##
## LEF for PtnCells ;
## created by Innovus v15.23-s045_1 on Fri Mar 20 17:59:08 2026
##

VERSION 5.8 ;

BUSBITCHARS "[]" ;
DIVIDERCHAR "/" ;

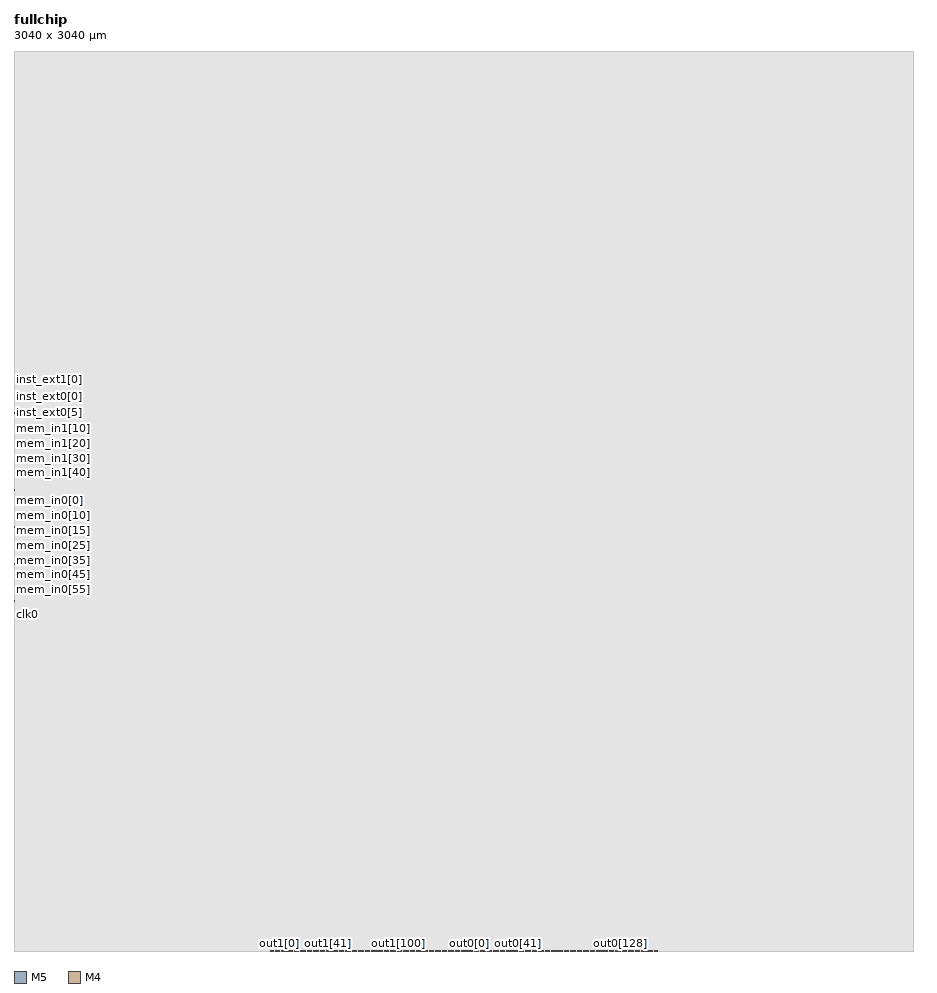
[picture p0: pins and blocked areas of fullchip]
MACRO fullchip
  CLASS BLOCK ;
  SIZE 3040.0000 BY 3040.0000 ;
  FOREIGN fullchip 0.0000 0.0000 ;
  ORIGIN 0 0 ;
  SYMMETRY X Y R90 ;
  PIN reset0
    DIRECTION INPUT ;
    USE SIGNAL ;
    PORT
      LAYER M5 ;
        RECT 0.0000 1147.1500 0.5200 1147.2500 ;
    END
  END reset0
  PIN reset1
    DIRECTION INPUT ;
    USE SIGNAL ;
    PORT
      LAYER M5 ;
        RECT 0.0000 1152.1500 0.5200 1152.2500 ;
    END
  END reset1
  PIN clk0
    DIRECTION INPUT ;
    USE SIGNAL ;
    PORT
      LAYER M5 ;
        RECT 0.0000 1137.1500 0.5200 1137.2500 ;
    END
  END clk0
  PIN clk1
    DIRECTION INPUT ;
    USE SIGNAL ;
    PORT
      LAYER M5 ;
        RECT 0.0000 1142.1500 0.5200 1142.2500 ;
    END
  END clk1
  PIN start0
    DIRECTION INPUT ;
    USE SIGNAL ;
    PORT
      LAYER M5 ;
        RECT 0.0000 1157.1500 0.5200 1157.2500 ;
    END
  END start0
  PIN start1
    DIRECTION INPUT ;
    USE SIGNAL ;
    PORT
      LAYER M5 ;
        RECT 0.0000 1162.1500 0.5200 1162.2500 ;
    END
  END start1
  PIN set_mode0
    DIRECTION INPUT ;
    USE SIGNAL ;
    PORT
      LAYER M5 ;
        RECT 0.0000 1167.1500 0.5200 1167.2500 ;
    END
  END set_mode0
  PIN set_mode1
    DIRECTION INPUT ;
    USE SIGNAL ;
    PORT
      LAYER M5 ;
        RECT 0.0000 1172.1500 0.5200 1172.2500 ;
    END
  END set_mode1
  PIN mode_in0[2]
    DIRECTION INPUT ;
    USE SIGNAL ;
    PORT
      LAYER M5 ;
        RECT 0.0000 1177.1500 0.5200 1177.2500 ;
    END
  END mode_in0[2]
  PIN mode_in0[1]
    DIRECTION INPUT ;
    USE SIGNAL ;
    PORT
      LAYER M5 ;
        RECT 0.0000 1182.1500 0.5200 1182.2500 ;
    END
  END mode_in0[1]
  PIN mode_in0[0]
    DIRECTION INPUT ;
    USE SIGNAL ;
    PORT
      LAYER M5 ;
        RECT 0.0000 1187.1500 0.5200 1187.2500 ;
    END
  END mode_in0[0]
  PIN mode_in1[2]
    DIRECTION INPUT ;
    USE SIGNAL ;
    PORT
      LAYER M5 ;
        RECT 0.0000 1192.1500 0.5200 1192.2500 ;
    END
  END mode_in1[2]
  PIN mode_in1[1]
    DIRECTION INPUT ;
    USE SIGNAL ;
    PORT
      LAYER M5 ;
        RECT 0.0000 1197.1500 0.5200 1197.2500 ;
    END
  END mode_in1[1]
  PIN mode_in1[0]
    DIRECTION INPUT ;
    USE SIGNAL ;
    PORT
      LAYER M5 ;
        RECT 0.0000 1202.1500 0.5200 1202.2500 ;
    END
  END mode_in1[0]
  PIN mem_in0[63]
    DIRECTION INPUT ;
    USE SIGNAL ;
    PORT
      LAYER M5 ;
        RECT 0.0000 1207.1500 0.5200 1207.2500 ;
    END
  END mem_in0[63]
  PIN mem_in0[62]
    DIRECTION INPUT ;
    USE SIGNAL ;
    PORT
      LAYER M5 ;
        RECT 0.0000 1212.1500 0.5200 1212.2500 ;
    END
  END mem_in0[62]
  PIN mem_in0[61]
    DIRECTION INPUT ;
    USE SIGNAL ;
    PORT
      LAYER M5 ;
        RECT 0.0000 1217.1500 0.5200 1217.2500 ;
    END
  END mem_in0[61]
  PIN mem_in0[60]
    DIRECTION INPUT ;
    USE SIGNAL ;
    PORT
      LAYER M5 ;
        RECT 0.0000 1222.1500 0.5200 1222.2500 ;
    END
  END mem_in0[60]
  PIN mem_in0[59]
    DIRECTION INPUT ;
    USE SIGNAL ;
    PORT
      LAYER M5 ;
        RECT 0.0000 1227.1500 0.5200 1227.2500 ;
    END
  END mem_in0[59]
  PIN mem_in0[58]
    DIRECTION INPUT ;
    USE SIGNAL ;
    PORT
      LAYER M5 ;
        RECT 0.0000 1232.1500 0.5200 1232.2500 ;
    END
  END mem_in0[58]
  PIN mem_in0[57]
    DIRECTION INPUT ;
    USE SIGNAL ;
    PORT
      LAYER M5 ;
        RECT 0.0000 1237.1500 0.5200 1237.2500 ;
    END
  END mem_in0[57]
  PIN mem_in0[56]
    DIRECTION INPUT ;
    USE SIGNAL ;
    PORT
      LAYER M5 ;
        RECT 0.0000 1242.1500 0.5200 1242.2500 ;
    END
  END mem_in0[56]
  PIN mem_in0[55]
    DIRECTION INPUT ;
    USE SIGNAL ;
    PORT
      LAYER M5 ;
        RECT 0.0000 1247.1500 0.5200 1247.2500 ;
    END
  END mem_in0[55]
  PIN mem_in0[54]
    DIRECTION INPUT ;
    USE SIGNAL ;
    PORT
      LAYER M5 ;
        RECT 0.0000 1252.1500 0.5200 1252.2500 ;
    END
  END mem_in0[54]
  PIN mem_in0[53]
    DIRECTION INPUT ;
    USE SIGNAL ;
    PORT
      LAYER M5 ;
        RECT 0.0000 1257.1500 0.5200 1257.2500 ;
    END
  END mem_in0[53]
  PIN mem_in0[52]
    DIRECTION INPUT ;
    USE SIGNAL ;
    PORT
      LAYER M5 ;
        RECT 0.0000 1262.1500 0.5200 1262.2500 ;
    END
  END mem_in0[52]
  PIN mem_in0[51]
    DIRECTION INPUT ;
    USE SIGNAL ;
    PORT
      LAYER M5 ;
        RECT 0.0000 1267.1500 0.5200 1267.2500 ;
    END
  END mem_in0[51]
  PIN mem_in0[50]
    DIRECTION INPUT ;
    USE SIGNAL ;
    PORT
      LAYER M5 ;
        RECT 0.0000 1272.1500 0.5200 1272.2500 ;
    END
  END mem_in0[50]
  PIN mem_in0[49]
    DIRECTION INPUT ;
    USE SIGNAL ;
    PORT
      LAYER M5 ;
        RECT 0.0000 1277.1500 0.5200 1277.2500 ;
    END
  END mem_in0[49]
  PIN mem_in0[48]
    DIRECTION INPUT ;
    USE SIGNAL ;
    PORT
      LAYER M5 ;
        RECT 0.0000 1282.1500 0.5200 1282.2500 ;
    END
  END mem_in0[48]
  PIN mem_in0[47]
    DIRECTION INPUT ;
    USE SIGNAL ;
    PORT
      LAYER M5 ;
        RECT 0.0000 1287.1500 0.5200 1287.2500 ;
    END
  END mem_in0[47]
  PIN mem_in0[46]
    DIRECTION INPUT ;
    USE SIGNAL ;
    PORT
      LAYER M5 ;
        RECT 0.0000 1292.1500 0.5200 1292.2500 ;
    END
  END mem_in0[46]
  PIN mem_in0[45]
    DIRECTION INPUT ;
    USE SIGNAL ;
    PORT
      LAYER M5 ;
        RECT 0.0000 1297.1500 0.5200 1297.2500 ;
    END
  END mem_in0[45]
  PIN mem_in0[44]
    DIRECTION INPUT ;
    USE SIGNAL ;
    PORT
      LAYER M5 ;
        RECT 0.0000 1302.1500 0.5200 1302.2500 ;
    END
  END mem_in0[44]
  PIN mem_in0[43]
    DIRECTION INPUT ;
    USE SIGNAL ;
    PORT
      LAYER M5 ;
        RECT 0.0000 1307.1500 0.5200 1307.2500 ;
    END
  END mem_in0[43]
  PIN mem_in0[42]
    DIRECTION INPUT ;
    USE SIGNAL ;
    PORT
      LAYER M5 ;
        RECT 0.0000 1312.1500 0.5200 1312.2500 ;
    END
  END mem_in0[42]
  PIN mem_in0[41]
    DIRECTION INPUT ;
    USE SIGNAL ;
    PORT
      LAYER M5 ;
        RECT 0.0000 1317.1500 0.5200 1317.2500 ;
    END
  END mem_in0[41]
  PIN mem_in0[40]
    DIRECTION INPUT ;
    USE SIGNAL ;
    PORT
      LAYER M5 ;
        RECT 0.0000 1322.1500 0.5200 1322.2500 ;
    END
  END mem_in0[40]
  PIN mem_in0[39]
    DIRECTION INPUT ;
    USE SIGNAL ;
    PORT
      LAYER M5 ;
        RECT 0.0000 1327.1500 0.5200 1327.2500 ;
    END
  END mem_in0[39]
  PIN mem_in0[38]
    DIRECTION INPUT ;
    USE SIGNAL ;
    PORT
      LAYER M5 ;
        RECT 0.0000 1332.1500 0.5200 1332.2500 ;
    END
  END mem_in0[38]
  PIN mem_in0[37]
    DIRECTION INPUT ;
    USE SIGNAL ;
    PORT
      LAYER M5 ;
        RECT 0.0000 1337.1500 0.5200 1337.2500 ;
    END
  END mem_in0[37]
  PIN mem_in0[36]
    DIRECTION INPUT ;
    USE SIGNAL ;
    PORT
      LAYER M5 ;
        RECT 0.0000 1342.1500 0.5200 1342.2500 ;
    END
  END mem_in0[36]
  PIN mem_in0[35]
    DIRECTION INPUT ;
    USE SIGNAL ;
    PORT
      LAYER M5 ;
        RECT 0.0000 1347.1500 0.5200 1347.2500 ;
    END
  END mem_in0[35]
  PIN mem_in0[34]
    DIRECTION INPUT ;
    USE SIGNAL ;
    PORT
      LAYER M5 ;
        RECT 0.0000 1352.1500 0.5200 1352.2500 ;
    END
  END mem_in0[34]
  PIN mem_in0[33]
    DIRECTION INPUT ;
    USE SIGNAL ;
    PORT
      LAYER M5 ;
        RECT 0.0000 1357.1500 0.5200 1357.2500 ;
    END
  END mem_in0[33]
  PIN mem_in0[32]
    DIRECTION INPUT ;
    USE SIGNAL ;
    PORT
      LAYER M5 ;
        RECT 0.0000 1362.1500 0.5200 1362.2500 ;
    END
  END mem_in0[32]
  PIN mem_in0[31]
    DIRECTION INPUT ;
    USE SIGNAL ;
    PORT
      LAYER M5 ;
        RECT 0.0000 1367.1500 0.5200 1367.2500 ;
    END
  END mem_in0[31]
  PIN mem_in0[30]
    DIRECTION INPUT ;
    USE SIGNAL ;
    PORT
      LAYER M5 ;
        RECT 0.0000 1372.1500 0.5200 1372.2500 ;
    END
  END mem_in0[30]
  PIN mem_in0[29]
    DIRECTION INPUT ;
    USE SIGNAL ;
    PORT
      LAYER M5 ;
        RECT 0.0000 1377.1500 0.5200 1377.2500 ;
    END
  END mem_in0[29]
  PIN mem_in0[28]
    DIRECTION INPUT ;
    USE SIGNAL ;
    PORT
      LAYER M5 ;
        RECT 0.0000 1382.1500 0.5200 1382.2500 ;
    END
  END mem_in0[28]
  PIN mem_in0[27]
    DIRECTION INPUT ;
    USE SIGNAL ;
    PORT
      LAYER M5 ;
        RECT 0.0000 1387.1500 0.5200 1387.2500 ;
    END
  END mem_in0[27]
  PIN mem_in0[26]
    DIRECTION INPUT ;
    USE SIGNAL ;
    PORT
      LAYER M5 ;
        RECT 0.0000 1392.1500 0.5200 1392.2500 ;
    END
  END mem_in0[26]
  PIN mem_in0[25]
    DIRECTION INPUT ;
    USE SIGNAL ;
    PORT
      LAYER M5 ;
        RECT 0.0000 1397.1500 0.5200 1397.2500 ;
    END
  END mem_in0[25]
  PIN mem_in0[24]
    DIRECTION INPUT ;
    USE SIGNAL ;
    PORT
      LAYER M5 ;
        RECT 0.0000 1402.1500 0.5200 1402.2500 ;
    END
  END mem_in0[24]
  PIN mem_in0[23]
    DIRECTION INPUT ;
    USE SIGNAL ;
    PORT
      LAYER M5 ;
        RECT 0.0000 1407.1500 0.5200 1407.2500 ;
    END
  END mem_in0[23]
  PIN mem_in0[22]
    DIRECTION INPUT ;
    USE SIGNAL ;
    PORT
      LAYER M5 ;
        RECT 0.0000 1412.1500 0.5200 1412.2500 ;
    END
  END mem_in0[22]
  PIN mem_in0[21]
    DIRECTION INPUT ;
    USE SIGNAL ;
    PORT
      LAYER M5 ;
        RECT 0.0000 1417.1500 0.5200 1417.2500 ;
    END
  END mem_in0[21]
  PIN mem_in0[20]
    DIRECTION INPUT ;
    USE SIGNAL ;
    PORT
      LAYER M5 ;
        RECT 0.0000 1422.1500 0.5200 1422.2500 ;
    END
  END mem_in0[20]
  PIN mem_in0[19]
    DIRECTION INPUT ;
    USE SIGNAL ;
    PORT
      LAYER M5 ;
        RECT 0.0000 1427.1500 0.5200 1427.2500 ;
    END
  END mem_in0[19]
  PIN mem_in0[18]
    DIRECTION INPUT ;
    USE SIGNAL ;
    PORT
      LAYER M5 ;
        RECT 0.0000 1432.1500 0.5200 1432.2500 ;
    END
  END mem_in0[18]
  PIN mem_in0[17]
    DIRECTION INPUT ;
    USE SIGNAL ;
    PORT
      LAYER M5 ;
        RECT 0.0000 1437.1500 0.5200 1437.2500 ;
    END
  END mem_in0[17]
  PIN mem_in0[16]
    DIRECTION INPUT ;
    USE SIGNAL ;
    PORT
      LAYER M5 ;
        RECT 0.0000 1442.1500 0.5200 1442.2500 ;
    END
  END mem_in0[16]
  PIN mem_in0[15]
    DIRECTION INPUT ;
    USE SIGNAL ;
    PORT
      LAYER M5 ;
        RECT 0.0000 1447.1500 0.5200 1447.2500 ;
    END
  END mem_in0[15]
  PIN mem_in0[14]
    DIRECTION INPUT ;
    USE SIGNAL ;
    PORT
      LAYER M5 ;
        RECT 0.0000 1452.1500 0.5200 1452.2500 ;
    END
  END mem_in0[14]
  PIN mem_in0[13]
    DIRECTION INPUT ;
    USE SIGNAL ;
    PORT
      LAYER M5 ;
        RECT 0.0000 1457.1500 0.5200 1457.2500 ;
    END
  END mem_in0[13]
  PIN mem_in0[12]
    DIRECTION INPUT ;
    USE SIGNAL ;
    PORT
      LAYER M5 ;
        RECT 0.0000 1462.1500 0.5200 1462.2500 ;
    END
  END mem_in0[12]
  PIN mem_in0[11]
    DIRECTION INPUT ;
    USE SIGNAL ;
    PORT
      LAYER M5 ;
        RECT 0.0000 1467.1500 0.5200 1467.2500 ;
    END
  END mem_in0[11]
  PIN mem_in0[10]
    DIRECTION INPUT ;
    USE SIGNAL ;
    PORT
      LAYER M5 ;
        RECT 0.0000 1472.1500 0.5200 1472.2500 ;
    END
  END mem_in0[10]
  PIN mem_in0[9]
    DIRECTION INPUT ;
    USE SIGNAL ;
    PORT
      LAYER M5 ;
        RECT 0.0000 1477.1500 0.5200 1477.2500 ;
    END
  END mem_in0[9]
  PIN mem_in0[8]
    DIRECTION INPUT ;
    USE SIGNAL ;
    PORT
      LAYER M5 ;
        RECT 0.0000 1482.1500 0.5200 1482.2500 ;
    END
  END mem_in0[8]
  PIN mem_in0[7]
    DIRECTION INPUT ;
    USE SIGNAL ;
    PORT
      LAYER M5 ;
        RECT 0.0000 1487.1500 0.5200 1487.2500 ;
    END
  END mem_in0[7]
  PIN mem_in0[6]
    DIRECTION INPUT ;
    USE SIGNAL ;
    PORT
      LAYER M5 ;
        RECT 0.0000 1492.1500 0.5200 1492.2500 ;
    END
  END mem_in0[6]
  PIN mem_in0[5]
    DIRECTION INPUT ;
    USE SIGNAL ;
    PORT
      LAYER M5 ;
        RECT 0.0000 1497.1500 0.5200 1497.2500 ;
    END
  END mem_in0[5]
  PIN mem_in0[4]
    DIRECTION INPUT ;
    USE SIGNAL ;
    PORT
      LAYER M5 ;
        RECT 0.0000 1502.1500 0.5200 1502.2500 ;
    END
  END mem_in0[4]
  PIN mem_in0[3]
    DIRECTION INPUT ;
    USE SIGNAL ;
    PORT
      LAYER M5 ;
        RECT 0.0000 1507.1500 0.5200 1507.2500 ;
    END
  END mem_in0[3]
  PIN mem_in0[2]
    DIRECTION INPUT ;
    USE SIGNAL ;
    PORT
      LAYER M5 ;
        RECT 0.0000 1512.1500 0.5200 1512.2500 ;
    END
  END mem_in0[2]
  PIN mem_in0[1]
    DIRECTION INPUT ;
    USE SIGNAL ;
    PORT
      LAYER M5 ;
        RECT 0.0000 1517.1500 0.5200 1517.2500 ;
    END
  END mem_in0[1]
  PIN mem_in0[0]
    DIRECTION INPUT ;
    USE SIGNAL ;
    PORT
      LAYER M5 ;
        RECT 0.0000 1522.1500 0.5200 1522.2500 ;
    END
  END mem_in0[0]
  PIN mem_in1[63]
    DIRECTION INPUT ;
    USE SIGNAL ;
    PORT
      LAYER M5 ;
        RECT 0.0000 1527.1500 0.5200 1527.2500 ;
    END
  END mem_in1[63]
  PIN mem_in1[62]
    DIRECTION INPUT ;
    USE SIGNAL ;
    PORT
      LAYER M5 ;
        RECT 0.0000 1532.1500 0.5200 1532.2500 ;
    END
  END mem_in1[62]
  PIN mem_in1[61]
    DIRECTION INPUT ;
    USE SIGNAL ;
    PORT
      LAYER M5 ;
        RECT 0.0000 1537.1500 0.5200 1537.2500 ;
    END
  END mem_in1[61]
  PIN mem_in1[60]
    DIRECTION INPUT ;
    USE SIGNAL ;
    PORT
      LAYER M5 ;
        RECT 0.0000 1542.1500 0.5200 1542.2500 ;
    END
  END mem_in1[60]
  PIN mem_in1[59]
    DIRECTION INPUT ;
    USE SIGNAL ;
    PORT
      LAYER M5 ;
        RECT 0.0000 1547.1500 0.5200 1547.2500 ;
    END
  END mem_in1[59]
  PIN mem_in1[58]
    DIRECTION INPUT ;
    USE SIGNAL ;
    PORT
      LAYER M5 ;
        RECT 0.0000 1552.1500 0.5200 1552.2500 ;
    END
  END mem_in1[58]
  PIN mem_in1[57]
    DIRECTION INPUT ;
    USE SIGNAL ;
    PORT
      LAYER M5 ;
        RECT 0.0000 1557.1500 0.5200 1557.2500 ;
    END
  END mem_in1[57]
  PIN mem_in1[56]
    DIRECTION INPUT ;
    USE SIGNAL ;
    PORT
      LAYER M5 ;
        RECT 0.0000 1562.1500 0.5200 1562.2500 ;
    END
  END mem_in1[56]
  PIN mem_in1[55]
    DIRECTION INPUT ;
    USE SIGNAL ;
    PORT
      LAYER M5 ;
        RECT 0.0000 1567.1500 0.5200 1567.2500 ;
    END
  END mem_in1[55]
  PIN mem_in1[54]
    DIRECTION INPUT ;
    USE SIGNAL ;
    PORT
      LAYER M5 ;
        RECT 0.0000 1572.1500 0.5200 1572.2500 ;
    END
  END mem_in1[54]
  PIN mem_in1[53]
    DIRECTION INPUT ;
    USE SIGNAL ;
    PORT
      LAYER M5 ;
        RECT 0.0000 1577.1500 0.5200 1577.2500 ;
    END
  END mem_in1[53]
  PIN mem_in1[52]
    DIRECTION INPUT ;
    USE SIGNAL ;
    PORT
      LAYER M5 ;
        RECT 0.0000 1582.1500 0.5200 1582.2500 ;
    END
  END mem_in1[52]
  PIN mem_in1[51]
    DIRECTION INPUT ;
    USE SIGNAL ;
    PORT
      LAYER M5 ;
        RECT 0.0000 1587.1500 0.5200 1587.2500 ;
    END
  END mem_in1[51]
  PIN mem_in1[50]
    DIRECTION INPUT ;
    USE SIGNAL ;
    PORT
      LAYER M5 ;
        RECT 0.0000 1592.1500 0.5200 1592.2500 ;
    END
  END mem_in1[50]
  PIN mem_in1[49]
    DIRECTION INPUT ;
    USE SIGNAL ;
    PORT
      LAYER M5 ;
        RECT 0.0000 1597.1500 0.5200 1597.2500 ;
    END
  END mem_in1[49]
  PIN mem_in1[48]
    DIRECTION INPUT ;
    USE SIGNAL ;
    PORT
      LAYER M5 ;
        RECT 0.0000 1602.1500 0.5200 1602.2500 ;
    END
  END mem_in1[48]
  PIN mem_in1[47]
    DIRECTION INPUT ;
    USE SIGNAL ;
    PORT
      LAYER M5 ;
        RECT 0.0000 1607.1500 0.5200 1607.2500 ;
    END
  END mem_in1[47]
  PIN mem_in1[46]
    DIRECTION INPUT ;
    USE SIGNAL ;
    PORT
      LAYER M5 ;
        RECT 0.0000 1612.1500 0.5200 1612.2500 ;
    END
  END mem_in1[46]
  PIN mem_in1[45]
    DIRECTION INPUT ;
    USE SIGNAL ;
    PORT
      LAYER M5 ;
        RECT 0.0000 1617.1500 0.5200 1617.2500 ;
    END
  END mem_in1[45]
  PIN mem_in1[44]
    DIRECTION INPUT ;
    USE SIGNAL ;
    PORT
      LAYER M5 ;
        RECT 0.0000 1622.1500 0.5200 1622.2500 ;
    END
  END mem_in1[44]
  PIN mem_in1[43]
    DIRECTION INPUT ;
    USE SIGNAL ;
    PORT
      LAYER M5 ;
        RECT 0.0000 1627.1500 0.5200 1627.2500 ;
    END
  END mem_in1[43]
  PIN mem_in1[42]
    DIRECTION INPUT ;
    USE SIGNAL ;
    PORT
      LAYER M5 ;
        RECT 0.0000 1632.1500 0.5200 1632.2500 ;
    END
  END mem_in1[42]
  PIN mem_in1[41]
    DIRECTION INPUT ;
    USE SIGNAL ;
    PORT
      LAYER M5 ;
        RECT 0.0000 1637.1500 0.5200 1637.2500 ;
    END
  END mem_in1[41]
  PIN mem_in1[40]
    DIRECTION INPUT ;
    USE SIGNAL ;
    PORT
      LAYER M5 ;
        RECT 0.0000 1642.1500 0.5200 1642.2500 ;
    END
  END mem_in1[40]
  PIN mem_in1[39]
    DIRECTION INPUT ;
    USE SIGNAL ;
    PORT
      LAYER M5 ;
        RECT 0.0000 1647.1500 0.5200 1647.2500 ;
    END
  END mem_in1[39]
  PIN mem_in1[38]
    DIRECTION INPUT ;
    USE SIGNAL ;
    PORT
      LAYER M5 ;
        RECT 0.0000 1652.1500 0.5200 1652.2500 ;
    END
  END mem_in1[38]
  PIN mem_in1[37]
    DIRECTION INPUT ;
    USE SIGNAL ;
    PORT
      LAYER M5 ;
        RECT 0.0000 1657.1500 0.5200 1657.2500 ;
    END
  END mem_in1[37]
  PIN mem_in1[36]
    DIRECTION INPUT ;
    USE SIGNAL ;
    PORT
      LAYER M5 ;
        RECT 0.0000 1662.1500 0.5200 1662.2500 ;
    END
  END mem_in1[36]
  PIN mem_in1[35]
    DIRECTION INPUT ;
    USE SIGNAL ;
    PORT
      LAYER M5 ;
        RECT 0.0000 1667.1500 0.5200 1667.2500 ;
    END
  END mem_in1[35]
  PIN mem_in1[34]
    DIRECTION INPUT ;
    USE SIGNAL ;
    PORT
      LAYER M5 ;
        RECT 0.0000 1672.1500 0.5200 1672.2500 ;
    END
  END mem_in1[34]
  PIN mem_in1[33]
    DIRECTION INPUT ;
    USE SIGNAL ;
    PORT
      LAYER M5 ;
        RECT 0.0000 1677.1500 0.5200 1677.2500 ;
    END
  END mem_in1[33]
  PIN mem_in1[32]
    DIRECTION INPUT ;
    USE SIGNAL ;
    PORT
      LAYER M5 ;
        RECT 0.0000 1682.1500 0.5200 1682.2500 ;
    END
  END mem_in1[32]
  PIN mem_in1[31]
    DIRECTION INPUT ;
    USE SIGNAL ;
    PORT
      LAYER M5 ;
        RECT 0.0000 1687.1500 0.5200 1687.2500 ;
    END
  END mem_in1[31]
  PIN mem_in1[30]
    DIRECTION INPUT ;
    USE SIGNAL ;
    PORT
      LAYER M5 ;
        RECT 0.0000 1692.1500 0.5200 1692.2500 ;
    END
  END mem_in1[30]
  PIN mem_in1[29]
    DIRECTION INPUT ;
    USE SIGNAL ;
    PORT
      LAYER M5 ;
        RECT 0.0000 1697.1500 0.5200 1697.2500 ;
    END
  END mem_in1[29]
  PIN mem_in1[28]
    DIRECTION INPUT ;
    USE SIGNAL ;
    PORT
      LAYER M5 ;
        RECT 0.0000 1702.1500 0.5200 1702.2500 ;
    END
  END mem_in1[28]
  PIN mem_in1[27]
    DIRECTION INPUT ;
    USE SIGNAL ;
    PORT
      LAYER M5 ;
        RECT 0.0000 1707.1500 0.5200 1707.2500 ;
    END
  END mem_in1[27]
  PIN mem_in1[26]
    DIRECTION INPUT ;
    USE SIGNAL ;
    PORT
      LAYER M5 ;
        RECT 0.0000 1712.1500 0.5200 1712.2500 ;
    END
  END mem_in1[26]
  PIN mem_in1[25]
    DIRECTION INPUT ;
    USE SIGNAL ;
    PORT
      LAYER M5 ;
        RECT 0.0000 1717.1500 0.5200 1717.2500 ;
    END
  END mem_in1[25]
  PIN mem_in1[24]
    DIRECTION INPUT ;
    USE SIGNAL ;
    PORT
      LAYER M5 ;
        RECT 0.0000 1722.1500 0.5200 1722.2500 ;
    END
  END mem_in1[24]
  PIN mem_in1[23]
    DIRECTION INPUT ;
    USE SIGNAL ;
    PORT
      LAYER M5 ;
        RECT 0.0000 1727.1500 0.5200 1727.2500 ;
    END
  END mem_in1[23]
  PIN mem_in1[22]
    DIRECTION INPUT ;
    USE SIGNAL ;
    PORT
      LAYER M5 ;
        RECT 0.0000 1732.1500 0.5200 1732.2500 ;
    END
  END mem_in1[22]
  PIN mem_in1[21]
    DIRECTION INPUT ;
    USE SIGNAL ;
    PORT
      LAYER M5 ;
        RECT 0.0000 1737.1500 0.5200 1737.2500 ;
    END
  END mem_in1[21]
  PIN mem_in1[20]
    DIRECTION INPUT ;
    USE SIGNAL ;
    PORT
      LAYER M5 ;
        RECT 0.0000 1742.1500 0.5200 1742.2500 ;
    END
  END mem_in1[20]
  PIN mem_in1[19]
    DIRECTION INPUT ;
    USE SIGNAL ;
    PORT
      LAYER M5 ;
        RECT 0.0000 1747.1500 0.5200 1747.2500 ;
    END
  END mem_in1[19]
  PIN mem_in1[18]
    DIRECTION INPUT ;
    USE SIGNAL ;
    PORT
      LAYER M5 ;
        RECT 0.0000 1752.1500 0.5200 1752.2500 ;
    END
  END mem_in1[18]
  PIN mem_in1[17]
    DIRECTION INPUT ;
    USE SIGNAL ;
    PORT
      LAYER M5 ;
        RECT 0.0000 1757.1500 0.5200 1757.2500 ;
    END
  END mem_in1[17]
  PIN mem_in1[16]
    DIRECTION INPUT ;
    USE SIGNAL ;
    PORT
      LAYER M5 ;
        RECT 0.0000 1762.1500 0.5200 1762.2500 ;
    END
  END mem_in1[16]
  PIN mem_in1[15]
    DIRECTION INPUT ;
    USE SIGNAL ;
    PORT
      LAYER M5 ;
        RECT 0.0000 1767.1500 0.5200 1767.2500 ;
    END
  END mem_in1[15]
  PIN mem_in1[14]
    DIRECTION INPUT ;
    USE SIGNAL ;
    PORT
      LAYER M5 ;
        RECT 0.0000 1772.1500 0.5200 1772.2500 ;
    END
  END mem_in1[14]
  PIN mem_in1[13]
    DIRECTION INPUT ;
    USE SIGNAL ;
    PORT
      LAYER M5 ;
        RECT 0.0000 1777.1500 0.5200 1777.2500 ;
    END
  END mem_in1[13]
  PIN mem_in1[12]
    DIRECTION INPUT ;
    USE SIGNAL ;
    PORT
      LAYER M5 ;
        RECT 0.0000 1782.1500 0.5200 1782.2500 ;
    END
  END mem_in1[12]
  PIN mem_in1[11]
    DIRECTION INPUT ;
    USE SIGNAL ;
    PORT
      LAYER M5 ;
        RECT 0.0000 1787.1500 0.5200 1787.2500 ;
    END
  END mem_in1[11]
  PIN mem_in1[10]
    DIRECTION INPUT ;
    USE SIGNAL ;
    PORT
      LAYER M5 ;
        RECT 0.0000 1792.1500 0.5200 1792.2500 ;
    END
  END mem_in1[10]
  PIN mem_in1[9]
    DIRECTION INPUT ;
    USE SIGNAL ;
    PORT
      LAYER M5 ;
        RECT 0.0000 1797.1500 0.5200 1797.2500 ;
    END
  END mem_in1[9]
  PIN mem_in1[8]
    DIRECTION INPUT ;
    USE SIGNAL ;
    PORT
      LAYER M5 ;
        RECT 0.0000 1802.1500 0.5200 1802.2500 ;
    END
  END mem_in1[8]
  PIN mem_in1[7]
    DIRECTION INPUT ;
    USE SIGNAL ;
    PORT
      LAYER M5 ;
        RECT 0.0000 1807.1500 0.5200 1807.2500 ;
    END
  END mem_in1[7]
  PIN mem_in1[6]
    DIRECTION INPUT ;
    USE SIGNAL ;
    PORT
      LAYER M5 ;
        RECT 0.0000 1812.1500 0.5200 1812.2500 ;
    END
  END mem_in1[6]
  PIN mem_in1[5]
    DIRECTION INPUT ;
    USE SIGNAL ;
    PORT
      LAYER M5 ;
        RECT 0.0000 1817.1500 0.5200 1817.2500 ;
    END
  END mem_in1[5]
  PIN mem_in1[4]
    DIRECTION INPUT ;
    USE SIGNAL ;
    PORT
      LAYER M5 ;
        RECT 0.0000 1822.1500 0.5200 1822.2500 ;
    END
  END mem_in1[4]
  PIN mem_in1[3]
    DIRECTION INPUT ;
    USE SIGNAL ;
    PORT
      LAYER M5 ;
        RECT 0.0000 1827.1500 0.5200 1827.2500 ;
    END
  END mem_in1[3]
  PIN mem_in1[2]
    DIRECTION INPUT ;
    USE SIGNAL ;
    PORT
      LAYER M5 ;
        RECT 0.0000 1832.1500 0.5200 1832.2500 ;
    END
  END mem_in1[2]
  PIN mem_in1[1]
    DIRECTION INPUT ;
    USE SIGNAL ;
    PORT
      LAYER M5 ;
        RECT 0.0000 1837.1500 0.5200 1837.2500 ;
    END
  END mem_in1[1]
  PIN mem_in1[0]
    DIRECTION INPUT ;
    USE SIGNAL ;
    PORT
      LAYER M5 ;
        RECT 0.0000 1842.1500 0.5200 1842.2500 ;
    END
  END mem_in1[0]
  PIN inst_ext0[5]
    DIRECTION INPUT ;
    USE SIGNAL ;
    PORT
      LAYER M5 ;
        RECT 0.0000 1847.1500 0.5200 1847.2500 ;
    END
  END inst_ext0[5]
  PIN inst_ext0[4]
    DIRECTION INPUT ;
    USE SIGNAL ;
    PORT
      LAYER M5 ;
        RECT 0.0000 1852.1500 0.5200 1852.2500 ;
    END
  END inst_ext0[4]
  PIN inst_ext0[3]
    DIRECTION INPUT ;
    USE SIGNAL ;
    PORT
      LAYER M5 ;
        RECT 0.0000 1857.1500 0.5200 1857.2500 ;
    END
  END inst_ext0[3]
  PIN inst_ext0[2]
    DIRECTION INPUT ;
    USE SIGNAL ;
    PORT
      LAYER M5 ;
        RECT 0.0000 1862.1500 0.5200 1862.2500 ;
    END
  END inst_ext0[2]
  PIN inst_ext0[1]
    DIRECTION INPUT ;
    USE SIGNAL ;
    PORT
      LAYER M5 ;
        RECT 0.0000 1867.1500 0.5200 1867.2500 ;
    END
  END inst_ext0[1]
  PIN inst_ext0[0]
    DIRECTION INPUT ;
    USE SIGNAL ;
    PORT
      LAYER M5 ;
        RECT 0.0000 1872.1500 0.5200 1872.2500 ;
    END
  END inst_ext0[0]
  PIN inst_ext1[5]
    DIRECTION INPUT ;
    USE SIGNAL ;
    PORT
      LAYER M5 ;
        RECT 0.0000 1877.1500 0.5200 1877.2500 ;
    END
  END inst_ext1[5]
  PIN inst_ext1[4]
    DIRECTION INPUT ;
    USE SIGNAL ;
    PORT
      LAYER M5 ;
        RECT 0.0000 1882.1500 0.5200 1882.2500 ;
    END
  END inst_ext1[4]
  PIN inst_ext1[3]
    DIRECTION INPUT ;
    USE SIGNAL ;
    PORT
      LAYER M5 ;
        RECT 0.0000 1887.1500 0.5200 1887.2500 ;
    END
  END inst_ext1[3]
  PIN inst_ext1[2]
    DIRECTION INPUT ;
    USE SIGNAL ;
    PORT
      LAYER M5 ;
        RECT 0.0000 1892.1500 0.5200 1892.2500 ;
    END
  END inst_ext1[2]
  PIN inst_ext1[1]
    DIRECTION INPUT ;
    USE SIGNAL ;
    PORT
      LAYER M5 ;
        RECT 0.0000 1897.1500 0.5200 1897.2500 ;
    END
  END inst_ext1[1]
  PIN inst_ext1[0]
    DIRECTION INPUT ;
    USE SIGNAL ;
    PORT
      LAYER M5 ;
        RECT 0.0000 1902.1500 0.5200 1902.2500 ;
    END
  END inst_ext1[0]
  PIN out0[159]
    DIRECTION OUTPUT ;
    USE SIGNAL ;
    PORT
      LAYER M4 ;
        RECT 2174.0500 0.0000 2174.1500 0.5200 ;
    END
  END out0[159]
  PIN out0[158]
    DIRECTION OUTPUT ;
    USE SIGNAL ;
    PORT
      LAYER M4 ;
        RECT 2170.0500 0.0000 2170.1500 0.5200 ;
    END
  END out0[158]
  PIN out0[157]
    DIRECTION OUTPUT ;
    USE SIGNAL ;
    PORT
      LAYER M4 ;
        RECT 2166.0500 0.0000 2166.1500 0.5200 ;
    END
  END out0[157]
  PIN out0[156]
    DIRECTION OUTPUT ;
    USE SIGNAL ;
    PORT
      LAYER M4 ;
        RECT 2162.0500 0.0000 2162.1500 0.5200 ;
    END
  END out0[156]
  PIN out0[155]
    DIRECTION OUTPUT ;
    USE SIGNAL ;
    PORT
      LAYER M4 ;
        RECT 2158.0500 0.0000 2158.1500 0.5200 ;
    END
  END out0[155]
  PIN out0[154]
    DIRECTION OUTPUT ;
    USE SIGNAL ;
    PORT
      LAYER M4 ;
        RECT 2154.0500 0.0000 2154.1500 0.5200 ;
    END
  END out0[154]
  PIN out0[153]
    DIRECTION OUTPUT ;
    USE SIGNAL ;
    PORT
      LAYER M4 ;
        RECT 2150.0500 0.0000 2150.1500 0.5200 ;
    END
  END out0[153]
  PIN out0[152]
    DIRECTION OUTPUT ;
    USE SIGNAL ;
    PORT
      LAYER M4 ;
        RECT 2146.0500 0.0000 2146.1500 0.5200 ;
    END
  END out0[152]
  PIN out0[151]
    DIRECTION OUTPUT ;
    USE SIGNAL ;
    PORT
      LAYER M4 ;
        RECT 2142.0500 0.0000 2142.1500 0.5200 ;
    END
  END out0[151]
  PIN out0[150]
    DIRECTION OUTPUT ;
    USE SIGNAL ;
    PORT
      LAYER M4 ;
        RECT 2138.0500 0.0000 2138.1500 0.5200 ;
    END
  END out0[150]
  PIN out0[149]
    DIRECTION OUTPUT ;
    USE SIGNAL ;
    PORT
      LAYER M4 ;
        RECT 2134.0500 0.0000 2134.1500 0.5200 ;
    END
  END out0[149]
  PIN out0[148]
    DIRECTION OUTPUT ;
    USE SIGNAL ;
    PORT
      LAYER M4 ;
        RECT 2130.0500 0.0000 2130.1500 0.5200 ;
    END
  END out0[148]
  PIN out0[147]
    DIRECTION OUTPUT ;
    USE SIGNAL ;
    PORT
      LAYER M4 ;
        RECT 2126.0500 0.0000 2126.1500 0.5200 ;
    END
  END out0[147]
  PIN out0[146]
    DIRECTION OUTPUT ;
    USE SIGNAL ;
    PORT
      LAYER M4 ;
        RECT 2122.0500 0.0000 2122.1500 0.5200 ;
    END
  END out0[146]
  PIN out0[145]
    DIRECTION OUTPUT ;
    USE SIGNAL ;
    PORT
      LAYER M4 ;
        RECT 2118.0500 0.0000 2118.1500 0.5200 ;
    END
  END out0[145]
  PIN out0[144]
    DIRECTION OUTPUT ;
    USE SIGNAL ;
    PORT
      LAYER M4 ;
        RECT 2114.0500 0.0000 2114.1500 0.5200 ;
    END
  END out0[144]
  PIN out0[143]
    DIRECTION OUTPUT ;
    USE SIGNAL ;
    PORT
      LAYER M4 ;
        RECT 2110.0500 0.0000 2110.1500 0.5200 ;
    END
  END out0[143]
  PIN out0[142]
    DIRECTION OUTPUT ;
    USE SIGNAL ;
    PORT
      LAYER M4 ;
        RECT 2106.0500 0.0000 2106.1500 0.5200 ;
    END
  END out0[142]
  PIN out0[141]
    DIRECTION OUTPUT ;
    USE SIGNAL ;
    PORT
      LAYER M4 ;
        RECT 2102.0500 0.0000 2102.1500 0.5200 ;
    END
  END out0[141]
  PIN out0[140]
    DIRECTION OUTPUT ;
    USE SIGNAL ;
    PORT
      LAYER M4 ;
        RECT 2098.0500 0.0000 2098.1500 0.5200 ;
    END
  END out0[140]
  PIN out0[139]
    DIRECTION OUTPUT ;
    USE SIGNAL ;
    PORT
      LAYER M4 ;
        RECT 2094.0500 0.0000 2094.1500 0.5200 ;
    END
  END out0[139]
  PIN out0[138]
    DIRECTION OUTPUT ;
    USE SIGNAL ;
    PORT
      LAYER M4 ;
        RECT 2090.0500 0.0000 2090.1500 0.5200 ;
    END
  END out0[138]
  PIN out0[137]
    DIRECTION OUTPUT ;
    USE SIGNAL ;
    PORT
      LAYER M4 ;
        RECT 2086.0500 0.0000 2086.1500 0.5200 ;
    END
  END out0[137]
  PIN out0[136]
    DIRECTION OUTPUT ;
    USE SIGNAL ;
    PORT
      LAYER M4 ;
        RECT 2082.0500 0.0000 2082.1500 0.5200 ;
    END
  END out0[136]
  PIN out0[135]
    DIRECTION OUTPUT ;
    USE SIGNAL ;
    PORT
      LAYER M4 ;
        RECT 2078.0500 0.0000 2078.1500 0.5200 ;
    END
  END out0[135]
  PIN out0[134]
    DIRECTION OUTPUT ;
    USE SIGNAL ;
    PORT
      LAYER M4 ;
        RECT 2074.0500 0.0000 2074.1500 0.5200 ;
    END
  END out0[134]
  PIN out0[133]
    DIRECTION OUTPUT ;
    USE SIGNAL ;
    PORT
      LAYER M4 ;
        RECT 2070.0500 0.0000 2070.1500 0.5200 ;
    END
  END out0[133]
  PIN out0[132]
    DIRECTION OUTPUT ;
    USE SIGNAL ;
    PORT
      LAYER M4 ;
        RECT 2066.0500 0.0000 2066.1500 0.5200 ;
    END
  END out0[132]
  PIN out0[131]
    DIRECTION OUTPUT ;
    USE SIGNAL ;
    PORT
      LAYER M4 ;
        RECT 2062.0500 0.0000 2062.1500 0.5200 ;
    END
  END out0[131]
  PIN out0[130]
    DIRECTION OUTPUT ;
    USE SIGNAL ;
    PORT
      LAYER M4 ;
        RECT 2058.0500 0.0000 2058.1500 0.5200 ;
    END
  END out0[130]
  PIN out0[129]
    DIRECTION OUTPUT ;
    USE SIGNAL ;
    PORT
      LAYER M4 ;
        RECT 2054.0500 0.0000 2054.1500 0.5200 ;
    END
  END out0[129]
  PIN out0[128]
    DIRECTION OUTPUT ;
    USE SIGNAL ;
    PORT
      LAYER M4 ;
        RECT 2050.0500 0.0000 2050.1500 0.5200 ;
    END
  END out0[128]
  PIN out0[127]
    DIRECTION OUTPUT ;
    USE SIGNAL ;
    PORT
      LAYER M4 ;
        RECT 2046.0500 0.0000 2046.1500 0.5200 ;
    END
  END out0[127]
  PIN out0[126]
    DIRECTION OUTPUT ;
    USE SIGNAL ;
    PORT
      LAYER M4 ;
        RECT 2042.0500 0.0000 2042.1500 0.5200 ;
    END
  END out0[126]
  PIN out0[125]
    DIRECTION OUTPUT ;
    USE SIGNAL ;
    PORT
      LAYER M4 ;
        RECT 2038.0500 0.0000 2038.1500 0.5200 ;
    END
  END out0[125]
  PIN out0[124]
    DIRECTION OUTPUT ;
    USE SIGNAL ;
    PORT
      LAYER M4 ;
        RECT 2034.0500 0.0000 2034.1500 0.5200 ;
    END
  END out0[124]
  PIN out0[123]
    DIRECTION OUTPUT ;
    USE SIGNAL ;
    PORT
      LAYER M4 ;
        RECT 2030.0500 0.0000 2030.1500 0.5200 ;
    END
  END out0[123]
  PIN out0[122]
    DIRECTION OUTPUT ;
    USE SIGNAL ;
    PORT
      LAYER M4 ;
        RECT 2026.0500 0.0000 2026.1500 0.5200 ;
    END
  END out0[122]
  PIN out0[121]
    DIRECTION OUTPUT ;
    USE SIGNAL ;
    PORT
      LAYER M4 ;
        RECT 2022.0500 0.0000 2022.1500 0.5200 ;
    END
  END out0[121]
  PIN out0[120]
    DIRECTION OUTPUT ;
    USE SIGNAL ;
    PORT
      LAYER M4 ;
        RECT 2018.0500 0.0000 2018.1500 0.5200 ;
    END
  END out0[120]
  PIN out0[119]
    DIRECTION OUTPUT ;
    USE SIGNAL ;
    PORT
      LAYER M4 ;
        RECT 2014.0500 0.0000 2014.1500 0.5200 ;
    END
  END out0[119]
  PIN out0[118]
    DIRECTION OUTPUT ;
    USE SIGNAL ;
    PORT
      LAYER M4 ;
        RECT 2010.0500 0.0000 2010.1500 0.5200 ;
    END
  END out0[118]
  PIN out0[117]
    DIRECTION OUTPUT ;
    USE SIGNAL ;
    PORT
      LAYER M4 ;
        RECT 2006.0500 0.0000 2006.1500 0.5200 ;
    END
  END out0[117]
  PIN out0[116]
    DIRECTION OUTPUT ;
    USE SIGNAL ;
    PORT
      LAYER M4 ;
        RECT 2002.0500 0.0000 2002.1500 0.5200 ;
    END
  END out0[116]
  PIN out0[115]
    DIRECTION OUTPUT ;
    USE SIGNAL ;
    PORT
      LAYER M4 ;
        RECT 1998.0500 0.0000 1998.1500 0.5200 ;
    END
  END out0[115]
  PIN out0[114]
    DIRECTION OUTPUT ;
    USE SIGNAL ;
    PORT
      LAYER M4 ;
        RECT 1994.0500 0.0000 1994.1500 0.5200 ;
    END
  END out0[114]
  PIN out0[113]
    DIRECTION OUTPUT ;
    USE SIGNAL ;
    PORT
      LAYER M4 ;
        RECT 1990.0500 0.0000 1990.1500 0.5200 ;
    END
  END out0[113]
  PIN out0[112]
    DIRECTION OUTPUT ;
    USE SIGNAL ;
    PORT
      LAYER M4 ;
        RECT 1986.0500 0.0000 1986.1500 0.5200 ;
    END
  END out0[112]
  PIN out0[111]
    DIRECTION OUTPUT ;
    USE SIGNAL ;
    PORT
      LAYER M4 ;
        RECT 1982.0500 0.0000 1982.1500 0.5200 ;
    END
  END out0[111]
  PIN out0[110]
    DIRECTION OUTPUT ;
    USE SIGNAL ;
    PORT
      LAYER M4 ;
        RECT 1978.0500 0.0000 1978.1500 0.5200 ;
    END
  END out0[110]
  PIN out0[109]
    DIRECTION OUTPUT ;
    USE SIGNAL ;
    PORT
      LAYER M4 ;
        RECT 1974.0500 0.0000 1974.1500 0.5200 ;
    END
  END out0[109]
  PIN out0[108]
    DIRECTION OUTPUT ;
    USE SIGNAL ;
    PORT
      LAYER M4 ;
        RECT 1970.0500 0.0000 1970.1500 0.5200 ;
    END
  END out0[108]
  PIN out0[107]
    DIRECTION OUTPUT ;
    USE SIGNAL ;
    PORT
      LAYER M4 ;
        RECT 1966.0500 0.0000 1966.1500 0.5200 ;
    END
  END out0[107]
  PIN out0[106]
    DIRECTION OUTPUT ;
    USE SIGNAL ;
    PORT
      LAYER M4 ;
        RECT 1962.0500 0.0000 1962.1500 0.5200 ;
    END
  END out0[106]
  PIN out0[105]
    DIRECTION OUTPUT ;
    USE SIGNAL ;
    PORT
      LAYER M4 ;
        RECT 1958.0500 0.0000 1958.1500 0.5200 ;
    END
  END out0[105]
  PIN out0[104]
    DIRECTION OUTPUT ;
    USE SIGNAL ;
    PORT
      LAYER M4 ;
        RECT 1954.0500 0.0000 1954.1500 0.5200 ;
    END
  END out0[104]
  PIN out0[103]
    DIRECTION OUTPUT ;
    USE SIGNAL ;
    PORT
      LAYER M4 ;
        RECT 1950.0500 0.0000 1950.1500 0.5200 ;
    END
  END out0[103]
  PIN out0[102]
    DIRECTION OUTPUT ;
    USE SIGNAL ;
    PORT
      LAYER M4 ;
        RECT 1946.0500 0.0000 1946.1500 0.5200 ;
    END
  END out0[102]
  PIN out0[101]
    DIRECTION OUTPUT ;
    USE SIGNAL ;
    PORT
      LAYER M4 ;
        RECT 1942.0500 0.0000 1942.1500 0.5200 ;
    END
  END out0[101]
  PIN out0[100]
    DIRECTION OUTPUT ;
    USE SIGNAL ;
    PORT
      LAYER M4 ;
        RECT 1938.0500 0.0000 1938.1500 0.5200 ;
    END
  END out0[100]
  PIN out0[99]
    DIRECTION OUTPUT ;
    USE SIGNAL ;
    PORT
      LAYER M4 ;
        RECT 1934.0500 0.0000 1934.1500 0.5200 ;
    END
  END out0[99]
  PIN out0[98]
    DIRECTION OUTPUT ;
    USE SIGNAL ;
    PORT
      LAYER M4 ;
        RECT 1930.0500 0.0000 1930.1500 0.5200 ;
    END
  END out0[98]
  PIN out0[97]
    DIRECTION OUTPUT ;
    USE SIGNAL ;
    PORT
      LAYER M4 ;
        RECT 1926.0500 0.0000 1926.1500 0.5200 ;
    END
  END out0[97]
  PIN out0[96]
    DIRECTION OUTPUT ;
    USE SIGNAL ;
    PORT
      LAYER M4 ;
        RECT 1922.0500 0.0000 1922.1500 0.5200 ;
    END
  END out0[96]
  PIN out0[95]
    DIRECTION OUTPUT ;
    USE SIGNAL ;
    PORT
      LAYER M4 ;
        RECT 1918.0500 0.0000 1918.1500 0.5200 ;
    END
  END out0[95]
  PIN out0[94]
    DIRECTION OUTPUT ;
    USE SIGNAL ;
    PORT
      LAYER M4 ;
        RECT 1914.0500 0.0000 1914.1500 0.5200 ;
    END
  END out0[94]
  PIN out0[93]
    DIRECTION OUTPUT ;
    USE SIGNAL ;
    PORT
      LAYER M4 ;
        RECT 1910.0500 0.0000 1910.1500 0.5200 ;
    END
  END out0[93]
  PIN out0[92]
    DIRECTION OUTPUT ;
    USE SIGNAL ;
    PORT
      LAYER M4 ;
        RECT 1906.0500 0.0000 1906.1500 0.5200 ;
    END
  END out0[92]
  PIN out0[91]
    DIRECTION OUTPUT ;
    USE SIGNAL ;
    PORT
      LAYER M4 ;
        RECT 1902.0500 0.0000 1902.1500 0.5200 ;
    END
  END out0[91]
  PIN out0[90]
    DIRECTION OUTPUT ;
    USE SIGNAL ;
    PORT
      LAYER M4 ;
        RECT 1898.0500 0.0000 1898.1500 0.5200 ;
    END
  END out0[90]
  PIN out0[89]
    DIRECTION OUTPUT ;
    USE SIGNAL ;
    PORT
      LAYER M4 ;
        RECT 1894.0500 0.0000 1894.1500 0.5200 ;
    END
  END out0[89]
  PIN out0[88]
    DIRECTION OUTPUT ;
    USE SIGNAL ;
    PORT
      LAYER M4 ;
        RECT 1890.0500 0.0000 1890.1500 0.5200 ;
    END
  END out0[88]
  PIN out0[87]
    DIRECTION OUTPUT ;
    USE SIGNAL ;
    PORT
      LAYER M4 ;
        RECT 1886.0500 0.0000 1886.1500 0.5200 ;
    END
  END out0[87]
  PIN out0[86]
    DIRECTION OUTPUT ;
    USE SIGNAL ;
    PORT
      LAYER M4 ;
        RECT 1882.0500 0.0000 1882.1500 0.5200 ;
    END
  END out0[86]
  PIN out0[85]
    DIRECTION OUTPUT ;
    USE SIGNAL ;
    PORT
      LAYER M4 ;
        RECT 1878.0500 0.0000 1878.1500 0.5200 ;
    END
  END out0[85]
  PIN out0[84]
    DIRECTION OUTPUT ;
    USE SIGNAL ;
    PORT
      LAYER M4 ;
        RECT 1874.0500 0.0000 1874.1500 0.5200 ;
    END
  END out0[84]
  PIN out0[83]
    DIRECTION OUTPUT ;
    USE SIGNAL ;
    PORT
      LAYER M4 ;
        RECT 1870.0500 0.0000 1870.1500 0.5200 ;
    END
  END out0[83]
  PIN out0[82]
    DIRECTION OUTPUT ;
    USE SIGNAL ;
    PORT
      LAYER M4 ;
        RECT 1866.0500 0.0000 1866.1500 0.5200 ;
    END
  END out0[82]
  PIN out0[81]
    DIRECTION OUTPUT ;
    USE SIGNAL ;
    PORT
      LAYER M4 ;
        RECT 1862.0500 0.0000 1862.1500 0.5200 ;
    END
  END out0[81]
  PIN out0[80]
    DIRECTION OUTPUT ;
    USE SIGNAL ;
    PORT
      LAYER M4 ;
        RECT 1858.0500 0.0000 1858.1500 0.5200 ;
    END
  END out0[80]
  PIN out0[79]
    DIRECTION OUTPUT ;
    USE SIGNAL ;
    PORT
      LAYER M4 ;
        RECT 1854.0500 0.0000 1854.1500 0.5200 ;
    END
  END out0[79]
  PIN out0[78]
    DIRECTION OUTPUT ;
    USE SIGNAL ;
    PORT
      LAYER M4 ;
        RECT 1850.0500 0.0000 1850.1500 0.5200 ;
    END
  END out0[78]
  PIN out0[77]
    DIRECTION OUTPUT ;
    USE SIGNAL ;
    PORT
      LAYER M4 ;
        RECT 1846.0500 0.0000 1846.1500 0.5200 ;
    END
  END out0[77]
  PIN out0[76]
    DIRECTION OUTPUT ;
    USE SIGNAL ;
    PORT
      LAYER M4 ;
        RECT 1842.0500 0.0000 1842.1500 0.5200 ;
    END
  END out0[76]
  PIN out0[75]
    DIRECTION OUTPUT ;
    USE SIGNAL ;
    PORT
      LAYER M4 ;
        RECT 1838.0500 0.0000 1838.1500 0.5200 ;
    END
  END out0[75]
  PIN out0[74]
    DIRECTION OUTPUT ;
    USE SIGNAL ;
    PORT
      LAYER M4 ;
        RECT 1834.0500 0.0000 1834.1500 0.5200 ;
    END
  END out0[74]
  PIN out0[73]
    DIRECTION OUTPUT ;
    USE SIGNAL ;
    PORT
      LAYER M4 ;
        RECT 1830.0500 0.0000 1830.1500 0.5200 ;
    END
  END out0[73]
  PIN out0[72]
    DIRECTION OUTPUT ;
    USE SIGNAL ;
    PORT
      LAYER M4 ;
        RECT 1826.0500 0.0000 1826.1500 0.5200 ;
    END
  END out0[72]
  PIN out0[71]
    DIRECTION OUTPUT ;
    USE SIGNAL ;
    PORT
      LAYER M4 ;
        RECT 1822.0500 0.0000 1822.1500 0.5200 ;
    END
  END out0[71]
  PIN out0[70]
    DIRECTION OUTPUT ;
    USE SIGNAL ;
    PORT
      LAYER M4 ;
        RECT 1818.0500 0.0000 1818.1500 0.5200 ;
    END
  END out0[70]
  PIN out0[69]
    DIRECTION OUTPUT ;
    USE SIGNAL ;
    PORT
      LAYER M4 ;
        RECT 1814.0500 0.0000 1814.1500 0.5200 ;
    END
  END out0[69]
  PIN out0[68]
    DIRECTION OUTPUT ;
    USE SIGNAL ;
    PORT
      LAYER M4 ;
        RECT 1810.0500 0.0000 1810.1500 0.5200 ;
    END
  END out0[68]
  PIN out0[67]
    DIRECTION OUTPUT ;
    USE SIGNAL ;
    PORT
      LAYER M4 ;
        RECT 1806.0500 0.0000 1806.1500 0.5200 ;
    END
  END out0[67]
  PIN out0[66]
    DIRECTION OUTPUT ;
    USE SIGNAL ;
    PORT
      LAYER M4 ;
        RECT 1802.0500 0.0000 1802.1500 0.5200 ;
    END
  END out0[66]
  PIN out0[65]
    DIRECTION OUTPUT ;
    USE SIGNAL ;
    PORT
      LAYER M4 ;
        RECT 1798.0500 0.0000 1798.1500 0.5200 ;
    END
  END out0[65]
  PIN out0[64]
    DIRECTION OUTPUT ;
    USE SIGNAL ;
    PORT
      LAYER M4 ;
        RECT 1794.0500 0.0000 1794.1500 0.5200 ;
    END
  END out0[64]
  PIN out0[63]
    DIRECTION OUTPUT ;
    USE SIGNAL ;
    PORT
      LAYER M4 ;
        RECT 1790.0500 0.0000 1790.1500 0.5200 ;
    END
  END out0[63]
  PIN out0[62]
    DIRECTION OUTPUT ;
    USE SIGNAL ;
    PORT
      LAYER M4 ;
        RECT 1786.0500 0.0000 1786.1500 0.5200 ;
    END
  END out0[62]
  PIN out0[61]
    DIRECTION OUTPUT ;
    USE SIGNAL ;
    PORT
      LAYER M4 ;
        RECT 1782.0500 0.0000 1782.1500 0.5200 ;
    END
  END out0[61]
  PIN out0[60]
    DIRECTION OUTPUT ;
    USE SIGNAL ;
    PORT
      LAYER M4 ;
        RECT 1778.0500 0.0000 1778.1500 0.5200 ;
    END
  END out0[60]
  PIN out0[59]
    DIRECTION OUTPUT ;
    USE SIGNAL ;
    PORT
      LAYER M4 ;
        RECT 1774.0500 0.0000 1774.1500 0.5200 ;
    END
  END out0[59]
  PIN out0[58]
    DIRECTION OUTPUT ;
    USE SIGNAL ;
    PORT
      LAYER M4 ;
        RECT 1770.0500 0.0000 1770.1500 0.5200 ;
    END
  END out0[58]
  PIN out0[57]
    DIRECTION OUTPUT ;
    USE SIGNAL ;
    PORT
      LAYER M4 ;
        RECT 1766.0500 0.0000 1766.1500 0.5200 ;
    END
  END out0[57]
  PIN out0[56]
    DIRECTION OUTPUT ;
    USE SIGNAL ;
    PORT
      LAYER M4 ;
        RECT 1762.0500 0.0000 1762.1500 0.5200 ;
    END
  END out0[56]
  PIN out0[55]
    DIRECTION OUTPUT ;
    USE SIGNAL ;
    PORT
      LAYER M4 ;
        RECT 1758.0500 0.0000 1758.1500 0.5200 ;
    END
  END out0[55]
  PIN out0[54]
    DIRECTION OUTPUT ;
    USE SIGNAL ;
    PORT
      LAYER M4 ;
        RECT 1754.0500 0.0000 1754.1500 0.5200 ;
    END
  END out0[54]
  PIN out0[53]
    DIRECTION OUTPUT ;
    USE SIGNAL ;
    PORT
      LAYER M4 ;
        RECT 1750.0500 0.0000 1750.1500 0.5200 ;
    END
  END out0[53]
  PIN out0[52]
    DIRECTION OUTPUT ;
    USE SIGNAL ;
    PORT
      LAYER M4 ;
        RECT 1746.0500 0.0000 1746.1500 0.5200 ;
    END
  END out0[52]
  PIN out0[51]
    DIRECTION OUTPUT ;
    USE SIGNAL ;
    PORT
      LAYER M4 ;
        RECT 1742.0500 0.0000 1742.1500 0.5200 ;
    END
  END out0[51]
  PIN out0[50]
    DIRECTION OUTPUT ;
    USE SIGNAL ;
    PORT
      LAYER M4 ;
        RECT 1738.0500 0.0000 1738.1500 0.5200 ;
    END
  END out0[50]
  PIN out0[49]
    DIRECTION OUTPUT ;
    USE SIGNAL ;
    PORT
      LAYER M4 ;
        RECT 1734.0500 0.0000 1734.1500 0.5200 ;
    END
  END out0[49]
  PIN out0[48]
    DIRECTION OUTPUT ;
    USE SIGNAL ;
    PORT
      LAYER M4 ;
        RECT 1730.0500 0.0000 1730.1500 0.5200 ;
    END
  END out0[48]
  PIN out0[47]
    DIRECTION OUTPUT ;
    USE SIGNAL ;
    PORT
      LAYER M4 ;
        RECT 1726.0500 0.0000 1726.1500 0.5200 ;
    END
  END out0[47]
  PIN out0[46]
    DIRECTION OUTPUT ;
    USE SIGNAL ;
    PORT
      LAYER M4 ;
        RECT 1722.0500 0.0000 1722.1500 0.5200 ;
    END
  END out0[46]
  PIN out0[45]
    DIRECTION OUTPUT ;
    USE SIGNAL ;
    PORT
      LAYER M4 ;
        RECT 1718.0500 0.0000 1718.1500 0.5200 ;
    END
  END out0[45]
  PIN out0[44]
    DIRECTION OUTPUT ;
    USE SIGNAL ;
    PORT
      LAYER M4 ;
        RECT 1714.0500 0.0000 1714.1500 0.5200 ;
    END
  END out0[44]
  PIN out0[43]
    DIRECTION OUTPUT ;
    USE SIGNAL ;
    PORT
      LAYER M4 ;
        RECT 1710.0500 0.0000 1710.1500 0.5200 ;
    END
  END out0[43]
  PIN out0[42]
    DIRECTION OUTPUT ;
    USE SIGNAL ;
    PORT
      LAYER M4 ;
        RECT 1706.0500 0.0000 1706.1500 0.5200 ;
    END
  END out0[42]
  PIN out0[41]
    DIRECTION OUTPUT ;
    USE SIGNAL ;
    PORT
      LAYER M4 ;
        RECT 1702.0500 0.0000 1702.1500 0.5200 ;
    END
  END out0[41]
  PIN out0[40]
    DIRECTION OUTPUT ;
    USE SIGNAL ;
    PORT
      LAYER M4 ;
        RECT 1698.0500 0.0000 1698.1500 0.5200 ;
    END
  END out0[40]
  PIN out0[39]
    DIRECTION OUTPUT ;
    USE SIGNAL ;
    PORT
      LAYER M4 ;
        RECT 1694.0500 0.0000 1694.1500 0.5200 ;
    END
  END out0[39]
  PIN out0[38]
    DIRECTION OUTPUT ;
    USE SIGNAL ;
    PORT
      LAYER M4 ;
        RECT 1690.0500 0.0000 1690.1500 0.5200 ;
    END
  END out0[38]
  PIN out0[37]
    DIRECTION OUTPUT ;
    USE SIGNAL ;
    PORT
      LAYER M4 ;
        RECT 1686.0500 0.0000 1686.1500 0.5200 ;
    END
  END out0[37]
  PIN out0[36]
    DIRECTION OUTPUT ;
    USE SIGNAL ;
    PORT
      LAYER M4 ;
        RECT 1682.0500 0.0000 1682.1500 0.5200 ;
    END
  END out0[36]
  PIN out0[35]
    DIRECTION OUTPUT ;
    USE SIGNAL ;
    PORT
      LAYER M4 ;
        RECT 1678.0500 0.0000 1678.1500 0.5200 ;
    END
  END out0[35]
  PIN out0[34]
    DIRECTION OUTPUT ;
    USE SIGNAL ;
    PORT
      LAYER M4 ;
        RECT 1674.0500 0.0000 1674.1500 0.5200 ;
    END
  END out0[34]
  PIN out0[33]
    DIRECTION OUTPUT ;
    USE SIGNAL ;
    PORT
      LAYER M4 ;
        RECT 1670.0500 0.0000 1670.1500 0.5200 ;
    END
  END out0[33]
  PIN out0[32]
    DIRECTION OUTPUT ;
    USE SIGNAL ;
    PORT
      LAYER M4 ;
        RECT 1666.0500 0.0000 1666.1500 0.5200 ;
    END
  END out0[32]
  PIN out0[31]
    DIRECTION OUTPUT ;
    USE SIGNAL ;
    PORT
      LAYER M4 ;
        RECT 1662.0500 0.0000 1662.1500 0.5200 ;
    END
  END out0[31]
  PIN out0[30]
    DIRECTION OUTPUT ;
    USE SIGNAL ;
    PORT
      LAYER M4 ;
        RECT 1658.0500 0.0000 1658.1500 0.5200 ;
    END
  END out0[30]
  PIN out0[29]
    DIRECTION OUTPUT ;
    USE SIGNAL ;
    PORT
      LAYER M4 ;
        RECT 1654.0500 0.0000 1654.1500 0.5200 ;
    END
  END out0[29]
  PIN out0[28]
    DIRECTION OUTPUT ;
    USE SIGNAL ;
    PORT
      LAYER M4 ;
        RECT 1650.0500 0.0000 1650.1500 0.5200 ;
    END
  END out0[28]
  PIN out0[27]
    DIRECTION OUTPUT ;
    USE SIGNAL ;
    PORT
      LAYER M4 ;
        RECT 1646.0500 0.0000 1646.1500 0.5200 ;
    END
  END out0[27]
  PIN out0[26]
    DIRECTION OUTPUT ;
    USE SIGNAL ;
    PORT
      LAYER M4 ;
        RECT 1642.0500 0.0000 1642.1500 0.5200 ;
    END
  END out0[26]
  PIN out0[25]
    DIRECTION OUTPUT ;
    USE SIGNAL ;
    PORT
      LAYER M4 ;
        RECT 1638.0500 0.0000 1638.1500 0.5200 ;
    END
  END out0[25]
  PIN out0[24]
    DIRECTION OUTPUT ;
    USE SIGNAL ;
    PORT
      LAYER M4 ;
        RECT 1634.0500 0.0000 1634.1500 0.5200 ;
    END
  END out0[24]
  PIN out0[23]
    DIRECTION OUTPUT ;
    USE SIGNAL ;
    PORT
      LAYER M4 ;
        RECT 1630.0500 0.0000 1630.1500 0.5200 ;
    END
  END out0[23]
  PIN out0[22]
    DIRECTION OUTPUT ;
    USE SIGNAL ;
    PORT
      LAYER M4 ;
        RECT 1626.0500 0.0000 1626.1500 0.5200 ;
    END
  END out0[22]
  PIN out0[21]
    DIRECTION OUTPUT ;
    USE SIGNAL ;
    PORT
      LAYER M4 ;
        RECT 1622.0500 0.0000 1622.1500 0.5200 ;
    END
  END out0[21]
  PIN out0[20]
    DIRECTION OUTPUT ;
    USE SIGNAL ;
    PORT
      LAYER M4 ;
        RECT 1618.0500 0.0000 1618.1500 0.5200 ;
    END
  END out0[20]
  PIN out0[19]
    DIRECTION OUTPUT ;
    USE SIGNAL ;
    PORT
      LAYER M4 ;
        RECT 1614.0500 0.0000 1614.1500 0.5200 ;
    END
  END out0[19]
  PIN out0[18]
    DIRECTION OUTPUT ;
    USE SIGNAL ;
    PORT
      LAYER M4 ;
        RECT 1610.0500 0.0000 1610.1500 0.5200 ;
    END
  END out0[18]
  PIN out0[17]
    DIRECTION OUTPUT ;
    USE SIGNAL ;
    PORT
      LAYER M4 ;
        RECT 1606.0500 0.0000 1606.1500 0.5200 ;
    END
  END out0[17]
  PIN out0[16]
    DIRECTION OUTPUT ;
    USE SIGNAL ;
    PORT
      LAYER M4 ;
        RECT 1602.0500 0.0000 1602.1500 0.5200 ;
    END
  END out0[16]
  PIN out0[15]
    DIRECTION OUTPUT ;
    USE SIGNAL ;
    PORT
      LAYER M4 ;
        RECT 1598.0500 0.0000 1598.1500 0.5200 ;
    END
  END out0[15]
  PIN out0[14]
    DIRECTION OUTPUT ;
    USE SIGNAL ;
    PORT
      LAYER M4 ;
        RECT 1594.0500 0.0000 1594.1500 0.5200 ;
    END
  END out0[14]
  PIN out0[13]
    DIRECTION OUTPUT ;
    USE SIGNAL ;
    PORT
      LAYER M4 ;
        RECT 1590.0500 0.0000 1590.1500 0.5200 ;
    END
  END out0[13]
  PIN out0[12]
    DIRECTION OUTPUT ;
    USE SIGNAL ;
    PORT
      LAYER M4 ;
        RECT 1586.0500 0.0000 1586.1500 0.5200 ;
    END
  END out0[12]
  PIN out0[11]
    DIRECTION OUTPUT ;
    USE SIGNAL ;
    PORT
      LAYER M4 ;
        RECT 1582.0500 0.0000 1582.1500 0.5200 ;
    END
  END out0[11]
  PIN out0[10]
    DIRECTION OUTPUT ;
    USE SIGNAL ;
    PORT
      LAYER M4 ;
        RECT 1578.0500 0.0000 1578.1500 0.5200 ;
    END
  END out0[10]
  PIN out0[9]
    DIRECTION OUTPUT ;
    USE SIGNAL ;
    PORT
      LAYER M4 ;
        RECT 1574.0500 0.0000 1574.1500 0.5200 ;
    END
  END out0[9]
  PIN out0[8]
    DIRECTION OUTPUT ;
    USE SIGNAL ;
    PORT
      LAYER M4 ;
        RECT 1570.0500 0.0000 1570.1500 0.5200 ;
    END
  END out0[8]
  PIN out0[7]
    DIRECTION OUTPUT ;
    USE SIGNAL ;
    PORT
      LAYER M4 ;
        RECT 1566.0500 0.0000 1566.1500 0.5200 ;
    END
  END out0[7]
  PIN out0[6]
    DIRECTION OUTPUT ;
    USE SIGNAL ;
    PORT
      LAYER M4 ;
        RECT 1562.0500 0.0000 1562.1500 0.5200 ;
    END
  END out0[6]
  PIN out0[5]
    DIRECTION OUTPUT ;
    USE SIGNAL ;
    PORT
      LAYER M4 ;
        RECT 1558.0500 0.0000 1558.1500 0.5200 ;
    END
  END out0[5]
  PIN out0[4]
    DIRECTION OUTPUT ;
    USE SIGNAL ;
    PORT
      LAYER M4 ;
        RECT 1554.0500 0.0000 1554.1500 0.5200 ;
    END
  END out0[4]
  PIN out0[3]
    DIRECTION OUTPUT ;
    USE SIGNAL ;
    PORT
      LAYER M4 ;
        RECT 1550.0500 0.0000 1550.1500 0.5200 ;
    END
  END out0[3]
  PIN out0[2]
    DIRECTION OUTPUT ;
    USE SIGNAL ;
    PORT
      LAYER M4 ;
        RECT 1546.0500 0.0000 1546.1500 0.5200 ;
    END
  END out0[2]
  PIN out0[1]
    DIRECTION OUTPUT ;
    USE SIGNAL ;
    PORT
      LAYER M4 ;
        RECT 1542.0500 0.0000 1542.1500 0.5200 ;
    END
  END out0[1]
  PIN out0[0]
    DIRECTION OUTPUT ;
    USE SIGNAL ;
    PORT
      LAYER M4 ;
        RECT 1538.0500 0.0000 1538.1500 0.5200 ;
    END
  END out0[0]
  PIN out1[159]
    DIRECTION OUTPUT ;
    USE SIGNAL ;
    PORT
      LAYER M4 ;
        RECT 1534.0500 0.0000 1534.1500 0.5200 ;
    END
  END out1[159]
  PIN out1[158]
    DIRECTION OUTPUT ;
    USE SIGNAL ;
    PORT
      LAYER M4 ;
        RECT 1530.0500 0.0000 1530.1500 0.5200 ;
    END
  END out1[158]
  PIN out1[157]
    DIRECTION OUTPUT ;
    USE SIGNAL ;
    PORT
      LAYER M4 ;
        RECT 1526.0500 0.0000 1526.1500 0.5200 ;
    END
  END out1[157]
  PIN out1[156]
    DIRECTION OUTPUT ;
    USE SIGNAL ;
    PORT
      LAYER M4 ;
        RECT 1522.0500 0.0000 1522.1500 0.5200 ;
    END
  END out1[156]
  PIN out1[155]
    DIRECTION OUTPUT ;
    USE SIGNAL ;
    PORT
      LAYER M4 ;
        RECT 1518.0500 0.0000 1518.1500 0.5200 ;
    END
  END out1[155]
  PIN out1[154]
    DIRECTION OUTPUT ;
    USE SIGNAL ;
    PORT
      LAYER M4 ;
        RECT 1514.0500 0.0000 1514.1500 0.5200 ;
    END
  END out1[154]
  PIN out1[153]
    DIRECTION OUTPUT ;
    USE SIGNAL ;
    PORT
      LAYER M4 ;
        RECT 1510.0500 0.0000 1510.1500 0.5200 ;
    END
  END out1[153]
  PIN out1[152]
    DIRECTION OUTPUT ;
    USE SIGNAL ;
    PORT
      LAYER M4 ;
        RECT 1506.0500 0.0000 1506.1500 0.5200 ;
    END
  END out1[152]
  PIN out1[151]
    DIRECTION OUTPUT ;
    USE SIGNAL ;
    PORT
      LAYER M4 ;
        RECT 1502.0500 0.0000 1502.1500 0.5200 ;
    END
  END out1[151]
  PIN out1[150]
    DIRECTION OUTPUT ;
    USE SIGNAL ;
    PORT
      LAYER M4 ;
        RECT 1498.0500 0.0000 1498.1500 0.5200 ;
    END
  END out1[150]
  PIN out1[149]
    DIRECTION OUTPUT ;
    USE SIGNAL ;
    PORT
      LAYER M4 ;
        RECT 1494.0500 0.0000 1494.1500 0.5200 ;
    END
  END out1[149]
  PIN out1[148]
    DIRECTION OUTPUT ;
    USE SIGNAL ;
    PORT
      LAYER M4 ;
        RECT 1490.0500 0.0000 1490.1500 0.5200 ;
    END
  END out1[148]
  PIN out1[147]
    DIRECTION OUTPUT ;
    USE SIGNAL ;
    PORT
      LAYER M4 ;
        RECT 1486.0500 0.0000 1486.1500 0.5200 ;
    END
  END out1[147]
  PIN out1[146]
    DIRECTION OUTPUT ;
    USE SIGNAL ;
    PORT
      LAYER M4 ;
        RECT 1482.0500 0.0000 1482.1500 0.5200 ;
    END
  END out1[146]
  PIN out1[145]
    DIRECTION OUTPUT ;
    USE SIGNAL ;
    PORT
      LAYER M4 ;
        RECT 1478.0500 0.0000 1478.1500 0.5200 ;
    END
  END out1[145]
  PIN out1[144]
    DIRECTION OUTPUT ;
    USE SIGNAL ;
    PORT
      LAYER M4 ;
        RECT 1474.0500 0.0000 1474.1500 0.5200 ;
    END
  END out1[144]
  PIN out1[143]
    DIRECTION OUTPUT ;
    USE SIGNAL ;
    PORT
      LAYER M4 ;
        RECT 1470.0500 0.0000 1470.1500 0.5200 ;
    END
  END out1[143]
  PIN out1[142]
    DIRECTION OUTPUT ;
    USE SIGNAL ;
    PORT
      LAYER M4 ;
        RECT 1466.0500 0.0000 1466.1500 0.5200 ;
    END
  END out1[142]
  PIN out1[141]
    DIRECTION OUTPUT ;
    USE SIGNAL ;
    PORT
      LAYER M4 ;
        RECT 1462.0500 0.0000 1462.1500 0.5200 ;
    END
  END out1[141]
  PIN out1[140]
    DIRECTION OUTPUT ;
    USE SIGNAL ;
    PORT
      LAYER M4 ;
        RECT 1458.0500 0.0000 1458.1500 0.5200 ;
    END
  END out1[140]
  PIN out1[139]
    DIRECTION OUTPUT ;
    USE SIGNAL ;
    PORT
      LAYER M4 ;
        RECT 1454.0500 0.0000 1454.1500 0.5200 ;
    END
  END out1[139]
  PIN out1[138]
    DIRECTION OUTPUT ;
    USE SIGNAL ;
    PORT
      LAYER M4 ;
        RECT 1450.0500 0.0000 1450.1500 0.5200 ;
    END
  END out1[138]
  PIN out1[137]
    DIRECTION OUTPUT ;
    USE SIGNAL ;
    PORT
      LAYER M4 ;
        RECT 1446.0500 0.0000 1446.1500 0.5200 ;
    END
  END out1[137]
  PIN out1[136]
    DIRECTION OUTPUT ;
    USE SIGNAL ;
    PORT
      LAYER M4 ;
        RECT 1442.0500 0.0000 1442.1500 0.5200 ;
    END
  END out1[136]
  PIN out1[135]
    DIRECTION OUTPUT ;
    USE SIGNAL ;
    PORT
      LAYER M4 ;
        RECT 1438.0500 0.0000 1438.1500 0.5200 ;
    END
  END out1[135]
  PIN out1[134]
    DIRECTION OUTPUT ;
    USE SIGNAL ;
    PORT
      LAYER M4 ;
        RECT 1434.0500 0.0000 1434.1500 0.5200 ;
    END
  END out1[134]
  PIN out1[133]
    DIRECTION OUTPUT ;
    USE SIGNAL ;
    PORT
      LAYER M4 ;
        RECT 1430.0500 0.0000 1430.1500 0.5200 ;
    END
  END out1[133]
  PIN out1[132]
    DIRECTION OUTPUT ;
    USE SIGNAL ;
    PORT
      LAYER M4 ;
        RECT 1426.0500 0.0000 1426.1500 0.5200 ;
    END
  END out1[132]
  PIN out1[131]
    DIRECTION OUTPUT ;
    USE SIGNAL ;
    PORT
      LAYER M4 ;
        RECT 1422.0500 0.0000 1422.1500 0.5200 ;
    END
  END out1[131]
  PIN out1[130]
    DIRECTION OUTPUT ;
    USE SIGNAL ;
    PORT
      LAYER M4 ;
        RECT 1418.0500 0.0000 1418.1500 0.5200 ;
    END
  END out1[130]
  PIN out1[129]
    DIRECTION OUTPUT ;
    USE SIGNAL ;
    PORT
      LAYER M4 ;
        RECT 1414.0500 0.0000 1414.1500 0.5200 ;
    END
  END out1[129]
  PIN out1[128]
    DIRECTION OUTPUT ;
    USE SIGNAL ;
    PORT
      LAYER M4 ;
        RECT 1410.0500 0.0000 1410.1500 0.5200 ;
    END
  END out1[128]
  PIN out1[127]
    DIRECTION OUTPUT ;
    USE SIGNAL ;
    PORT
      LAYER M4 ;
        RECT 1406.0500 0.0000 1406.1500 0.5200 ;
    END
  END out1[127]
  PIN out1[126]
    DIRECTION OUTPUT ;
    USE SIGNAL ;
    PORT
      LAYER M4 ;
        RECT 1402.0500 0.0000 1402.1500 0.5200 ;
    END
  END out1[126]
  PIN out1[125]
    DIRECTION OUTPUT ;
    USE SIGNAL ;
    PORT
      LAYER M4 ;
        RECT 1398.0500 0.0000 1398.1500 0.5200 ;
    END
  END out1[125]
  PIN out1[124]
    DIRECTION OUTPUT ;
    USE SIGNAL ;
    PORT
      LAYER M4 ;
        RECT 1394.0500 0.0000 1394.1500 0.5200 ;
    END
  END out1[124]
  PIN out1[123]
    DIRECTION OUTPUT ;
    USE SIGNAL ;
    PORT
      LAYER M4 ;
        RECT 1390.0500 0.0000 1390.1500 0.5200 ;
    END
  END out1[123]
  PIN out1[122]
    DIRECTION OUTPUT ;
    USE SIGNAL ;
    PORT
      LAYER M4 ;
        RECT 1386.0500 0.0000 1386.1500 0.5200 ;
    END
  END out1[122]
  PIN out1[121]
    DIRECTION OUTPUT ;
    USE SIGNAL ;
    PORT
      LAYER M4 ;
        RECT 1382.0500 0.0000 1382.1500 0.5200 ;
    END
  END out1[121]
  PIN out1[120]
    DIRECTION OUTPUT ;
    USE SIGNAL ;
    PORT
      LAYER M4 ;
        RECT 1378.0500 0.0000 1378.1500 0.5200 ;
    END
  END out1[120]
  PIN out1[119]
    DIRECTION OUTPUT ;
    USE SIGNAL ;
    PORT
      LAYER M4 ;
        RECT 1374.0500 0.0000 1374.1500 0.5200 ;
    END
  END out1[119]
  PIN out1[118]
    DIRECTION OUTPUT ;
    USE SIGNAL ;
    PORT
      LAYER M4 ;
        RECT 1370.0500 0.0000 1370.1500 0.5200 ;
    END
  END out1[118]
  PIN out1[117]
    DIRECTION OUTPUT ;
    USE SIGNAL ;
    PORT
      LAYER M4 ;
        RECT 1366.0500 0.0000 1366.1500 0.5200 ;
    END
  END out1[117]
  PIN out1[116]
    DIRECTION OUTPUT ;
    USE SIGNAL ;
    PORT
      LAYER M4 ;
        RECT 1362.0500 0.0000 1362.1500 0.5200 ;
    END
  END out1[116]
  PIN out1[115]
    DIRECTION OUTPUT ;
    USE SIGNAL ;
    PORT
      LAYER M4 ;
        RECT 1358.0500 0.0000 1358.1500 0.5200 ;
    END
  END out1[115]
  PIN out1[114]
    DIRECTION OUTPUT ;
    USE SIGNAL ;
    PORT
      LAYER M4 ;
        RECT 1354.0500 0.0000 1354.1500 0.5200 ;
    END
  END out1[114]
  PIN out1[113]
    DIRECTION OUTPUT ;
    USE SIGNAL ;
    PORT
      LAYER M4 ;
        RECT 1350.0500 0.0000 1350.1500 0.5200 ;
    END
  END out1[113]
  PIN out1[112]
    DIRECTION OUTPUT ;
    USE SIGNAL ;
    PORT
      LAYER M4 ;
        RECT 1346.0500 0.0000 1346.1500 0.5200 ;
    END
  END out1[112]
  PIN out1[111]
    DIRECTION OUTPUT ;
    USE SIGNAL ;
    PORT
      LAYER M4 ;
        RECT 1342.0500 0.0000 1342.1500 0.5200 ;
    END
  END out1[111]
  PIN out1[110]
    DIRECTION OUTPUT ;
    USE SIGNAL ;
    PORT
      LAYER M4 ;
        RECT 1338.0500 0.0000 1338.1500 0.5200 ;
    END
  END out1[110]
  PIN out1[109]
    DIRECTION OUTPUT ;
    USE SIGNAL ;
    PORT
      LAYER M4 ;
        RECT 1334.0500 0.0000 1334.1500 0.5200 ;
    END
  END out1[109]
  PIN out1[108]
    DIRECTION OUTPUT ;
    USE SIGNAL ;
    PORT
      LAYER M4 ;
        RECT 1330.0500 0.0000 1330.1500 0.5200 ;
    END
  END out1[108]
  PIN out1[107]
    DIRECTION OUTPUT ;
    USE SIGNAL ;
    PORT
      LAYER M4 ;
        RECT 1326.0500 0.0000 1326.1500 0.5200 ;
    END
  END out1[107]
  PIN out1[106]
    DIRECTION OUTPUT ;
    USE SIGNAL ;
    PORT
      LAYER M4 ;
        RECT 1322.0500 0.0000 1322.1500 0.5200 ;
    END
  END out1[106]
  PIN out1[105]
    DIRECTION OUTPUT ;
    USE SIGNAL ;
    PORT
      LAYER M4 ;
        RECT 1318.0500 0.0000 1318.1500 0.5200 ;
    END
  END out1[105]
  PIN out1[104]
    DIRECTION OUTPUT ;
    USE SIGNAL ;
    PORT
      LAYER M4 ;
        RECT 1314.0500 0.0000 1314.1500 0.5200 ;
    END
  END out1[104]
  PIN out1[103]
    DIRECTION OUTPUT ;
    USE SIGNAL ;
    PORT
      LAYER M4 ;
        RECT 1310.0500 0.0000 1310.1500 0.5200 ;
    END
  END out1[103]
  PIN out1[102]
    DIRECTION OUTPUT ;
    USE SIGNAL ;
    PORT
      LAYER M4 ;
        RECT 1306.0500 0.0000 1306.1500 0.5200 ;
    END
  END out1[102]
  PIN out1[101]
    DIRECTION OUTPUT ;
    USE SIGNAL ;
    PORT
      LAYER M4 ;
        RECT 1302.0500 0.0000 1302.1500 0.5200 ;
    END
  END out1[101]
  PIN out1[100]
    DIRECTION OUTPUT ;
    USE SIGNAL ;
    PORT
      LAYER M4 ;
        RECT 1298.0500 0.0000 1298.1500 0.5200 ;
    END
  END out1[100]
  PIN out1[99]
    DIRECTION OUTPUT ;
    USE SIGNAL ;
    PORT
      LAYER M4 ;
        RECT 1294.0500 0.0000 1294.1500 0.5200 ;
    END
  END out1[99]
  PIN out1[98]
    DIRECTION OUTPUT ;
    USE SIGNAL ;
    PORT
      LAYER M4 ;
        RECT 1290.0500 0.0000 1290.1500 0.5200 ;
    END
  END out1[98]
  PIN out1[97]
    DIRECTION OUTPUT ;
    USE SIGNAL ;
    PORT
      LAYER M4 ;
        RECT 1286.0500 0.0000 1286.1500 0.5200 ;
    END
  END out1[97]
  PIN out1[96]
    DIRECTION OUTPUT ;
    USE SIGNAL ;
    PORT
      LAYER M4 ;
        RECT 1282.0500 0.0000 1282.1500 0.5200 ;
    END
  END out1[96]
  PIN out1[95]
    DIRECTION OUTPUT ;
    USE SIGNAL ;
    PORT
      LAYER M4 ;
        RECT 1278.0500 0.0000 1278.1500 0.5200 ;
    END
  END out1[95]
  PIN out1[94]
    DIRECTION OUTPUT ;
    USE SIGNAL ;
    PORT
      LAYER M4 ;
        RECT 1274.0500 0.0000 1274.1500 0.5200 ;
    END
  END out1[94]
  PIN out1[93]
    DIRECTION OUTPUT ;
    USE SIGNAL ;
    PORT
      LAYER M4 ;
        RECT 1270.0500 0.0000 1270.1500 0.5200 ;
    END
  END out1[93]
  PIN out1[92]
    DIRECTION OUTPUT ;
    USE SIGNAL ;
    PORT
      LAYER M4 ;
        RECT 1266.0500 0.0000 1266.1500 0.5200 ;
    END
  END out1[92]
  PIN out1[91]
    DIRECTION OUTPUT ;
    USE SIGNAL ;
    PORT
      LAYER M4 ;
        RECT 1262.0500 0.0000 1262.1500 0.5200 ;
    END
  END out1[91]
  PIN out1[90]
    DIRECTION OUTPUT ;
    USE SIGNAL ;
    PORT
      LAYER M4 ;
        RECT 1258.0500 0.0000 1258.1500 0.5200 ;
    END
  END out1[90]
  PIN out1[89]
    DIRECTION OUTPUT ;
    USE SIGNAL ;
    PORT
      LAYER M4 ;
        RECT 1254.0500 0.0000 1254.1500 0.5200 ;
    END
  END out1[89]
  PIN out1[88]
    DIRECTION OUTPUT ;
    USE SIGNAL ;
    PORT
      LAYER M4 ;
        RECT 1250.0500 0.0000 1250.1500 0.5200 ;
    END
  END out1[88]
  PIN out1[87]
    DIRECTION OUTPUT ;
    USE SIGNAL ;
    PORT
      LAYER M4 ;
        RECT 1246.0500 0.0000 1246.1500 0.5200 ;
    END
  END out1[87]
  PIN out1[86]
    DIRECTION OUTPUT ;
    USE SIGNAL ;
    PORT
      LAYER M4 ;
        RECT 1242.0500 0.0000 1242.1500 0.5200 ;
    END
  END out1[86]
  PIN out1[85]
    DIRECTION OUTPUT ;
    USE SIGNAL ;
    PORT
      LAYER M4 ;
        RECT 1238.0500 0.0000 1238.1500 0.5200 ;
    END
  END out1[85]
  PIN out1[84]
    DIRECTION OUTPUT ;
    USE SIGNAL ;
    PORT
      LAYER M4 ;
        RECT 1234.0500 0.0000 1234.1500 0.5200 ;
    END
  END out1[84]
  PIN out1[83]
    DIRECTION OUTPUT ;
    USE SIGNAL ;
    PORT
      LAYER M4 ;
        RECT 1230.0500 0.0000 1230.1500 0.5200 ;
    END
  END out1[83]
  PIN out1[82]
    DIRECTION OUTPUT ;
    USE SIGNAL ;
    PORT
      LAYER M4 ;
        RECT 1226.0500 0.0000 1226.1500 0.5200 ;
    END
  END out1[82]
  PIN out1[81]
    DIRECTION OUTPUT ;
    USE SIGNAL ;
    PORT
      LAYER M4 ;
        RECT 1222.0500 0.0000 1222.1500 0.5200 ;
    END
  END out1[81]
  PIN out1[80]
    DIRECTION OUTPUT ;
    USE SIGNAL ;
    PORT
      LAYER M4 ;
        RECT 1218.0500 0.0000 1218.1500 0.5200 ;
    END
  END out1[80]
  PIN out1[79]
    DIRECTION OUTPUT ;
    USE SIGNAL ;
    PORT
      LAYER M4 ;
        RECT 1214.0500 0.0000 1214.1500 0.5200 ;
    END
  END out1[79]
  PIN out1[78]
    DIRECTION OUTPUT ;
    USE SIGNAL ;
    PORT
      LAYER M4 ;
        RECT 1210.0500 0.0000 1210.1500 0.5200 ;
    END
  END out1[78]
  PIN out1[77]
    DIRECTION OUTPUT ;
    USE SIGNAL ;
    PORT
      LAYER M4 ;
        RECT 1206.0500 0.0000 1206.1500 0.5200 ;
    END
  END out1[77]
  PIN out1[76]
    DIRECTION OUTPUT ;
    USE SIGNAL ;
    PORT
      LAYER M4 ;
        RECT 1202.0500 0.0000 1202.1500 0.5200 ;
    END
  END out1[76]
  PIN out1[75]
    DIRECTION OUTPUT ;
    USE SIGNAL ;
    PORT
      LAYER M4 ;
        RECT 1198.0500 0.0000 1198.1500 0.5200 ;
    END
  END out1[75]
  PIN out1[74]
    DIRECTION OUTPUT ;
    USE SIGNAL ;
    PORT
      LAYER M4 ;
        RECT 1194.0500 0.0000 1194.1500 0.5200 ;
    END
  END out1[74]
  PIN out1[73]
    DIRECTION OUTPUT ;
    USE SIGNAL ;
    PORT
      LAYER M4 ;
        RECT 1190.0500 0.0000 1190.1500 0.5200 ;
    END
  END out1[73]
  PIN out1[72]
    DIRECTION OUTPUT ;
    USE SIGNAL ;
    PORT
      LAYER M4 ;
        RECT 1186.0500 0.0000 1186.1500 0.5200 ;
    END
  END out1[72]
  PIN out1[71]
    DIRECTION OUTPUT ;
    USE SIGNAL ;
    PORT
      LAYER M4 ;
        RECT 1182.0500 0.0000 1182.1500 0.5200 ;
    END
  END out1[71]
  PIN out1[70]
    DIRECTION OUTPUT ;
    USE SIGNAL ;
    PORT
      LAYER M4 ;
        RECT 1178.0500 0.0000 1178.1500 0.5200 ;
    END
  END out1[70]
  PIN out1[69]
    DIRECTION OUTPUT ;
    USE SIGNAL ;
    PORT
      LAYER M4 ;
        RECT 1174.0500 0.0000 1174.1500 0.5200 ;
    END
  END out1[69]
  PIN out1[68]
    DIRECTION OUTPUT ;
    USE SIGNAL ;
    PORT
      LAYER M4 ;
        RECT 1170.0500 0.0000 1170.1500 0.5200 ;
    END
  END out1[68]
  PIN out1[67]
    DIRECTION OUTPUT ;
    USE SIGNAL ;
    PORT
      LAYER M4 ;
        RECT 1166.0500 0.0000 1166.1500 0.5200 ;
    END
  END out1[67]
  PIN out1[66]
    DIRECTION OUTPUT ;
    USE SIGNAL ;
    PORT
      LAYER M4 ;
        RECT 1162.0500 0.0000 1162.1500 0.5200 ;
    END
  END out1[66]
  PIN out1[65]
    DIRECTION OUTPUT ;
    USE SIGNAL ;
    PORT
      LAYER M4 ;
        RECT 1158.0500 0.0000 1158.1500 0.5200 ;
    END
  END out1[65]
  PIN out1[64]
    DIRECTION OUTPUT ;
    USE SIGNAL ;
    PORT
      LAYER M4 ;
        RECT 1154.0500 0.0000 1154.1500 0.5200 ;
    END
  END out1[64]
  PIN out1[63]
    DIRECTION OUTPUT ;
    USE SIGNAL ;
    PORT
      LAYER M4 ;
        RECT 1150.0500 0.0000 1150.1500 0.5200 ;
    END
  END out1[63]
  PIN out1[62]
    DIRECTION OUTPUT ;
    USE SIGNAL ;
    PORT
      LAYER M4 ;
        RECT 1146.0500 0.0000 1146.1500 0.5200 ;
    END
  END out1[62]
  PIN out1[61]
    DIRECTION OUTPUT ;
    USE SIGNAL ;
    PORT
      LAYER M4 ;
        RECT 1142.0500 0.0000 1142.1500 0.5200 ;
    END
  END out1[61]
  PIN out1[60]
    DIRECTION OUTPUT ;
    USE SIGNAL ;
    PORT
      LAYER M4 ;
        RECT 1138.0500 0.0000 1138.1500 0.5200 ;
    END
  END out1[60]
  PIN out1[59]
    DIRECTION OUTPUT ;
    USE SIGNAL ;
    PORT
      LAYER M4 ;
        RECT 1134.0500 0.0000 1134.1500 0.5200 ;
    END
  END out1[59]
  PIN out1[58]
    DIRECTION OUTPUT ;
    USE SIGNAL ;
    PORT
      LAYER M4 ;
        RECT 1130.0500 0.0000 1130.1500 0.5200 ;
    END
  END out1[58]
  PIN out1[57]
    DIRECTION OUTPUT ;
    USE SIGNAL ;
    PORT
      LAYER M4 ;
        RECT 1126.0500 0.0000 1126.1500 0.5200 ;
    END
  END out1[57]
  PIN out1[56]
    DIRECTION OUTPUT ;
    USE SIGNAL ;
    PORT
      LAYER M4 ;
        RECT 1122.0500 0.0000 1122.1500 0.5200 ;
    END
  END out1[56]
  PIN out1[55]
    DIRECTION OUTPUT ;
    USE SIGNAL ;
    PORT
      LAYER M4 ;
        RECT 1118.0500 0.0000 1118.1500 0.5200 ;
    END
  END out1[55]
  PIN out1[54]
    DIRECTION OUTPUT ;
    USE SIGNAL ;
    PORT
      LAYER M4 ;
        RECT 1114.0500 0.0000 1114.1500 0.5200 ;
    END
  END out1[54]
  PIN out1[53]
    DIRECTION OUTPUT ;
    USE SIGNAL ;
    PORT
      LAYER M4 ;
        RECT 1110.0500 0.0000 1110.1500 0.5200 ;
    END
  END out1[53]
  PIN out1[52]
    DIRECTION OUTPUT ;
    USE SIGNAL ;
    PORT
      LAYER M4 ;
        RECT 1106.0500 0.0000 1106.1500 0.5200 ;
    END
  END out1[52]
  PIN out1[51]
    DIRECTION OUTPUT ;
    USE SIGNAL ;
    PORT
      LAYER M4 ;
        RECT 1102.0500 0.0000 1102.1500 0.5200 ;
    END
  END out1[51]
  PIN out1[50]
    DIRECTION OUTPUT ;
    USE SIGNAL ;
    PORT
      LAYER M4 ;
        RECT 1098.0500 0.0000 1098.1500 0.5200 ;
    END
  END out1[50]
  PIN out1[49]
    DIRECTION OUTPUT ;
    USE SIGNAL ;
    PORT
      LAYER M4 ;
        RECT 1094.0500 0.0000 1094.1500 0.5200 ;
    END
  END out1[49]
  PIN out1[48]
    DIRECTION OUTPUT ;
    USE SIGNAL ;
    PORT
      LAYER M4 ;
        RECT 1090.0500 0.0000 1090.1500 0.5200 ;
    END
  END out1[48]
  PIN out1[47]
    DIRECTION OUTPUT ;
    USE SIGNAL ;
    PORT
      LAYER M4 ;
        RECT 1086.0500 0.0000 1086.1500 0.5200 ;
    END
  END out1[47]
  PIN out1[46]
    DIRECTION OUTPUT ;
    USE SIGNAL ;
    PORT
      LAYER M4 ;
        RECT 1082.0500 0.0000 1082.1500 0.5200 ;
    END
  END out1[46]
  PIN out1[45]
    DIRECTION OUTPUT ;
    USE SIGNAL ;
    PORT
      LAYER M4 ;
        RECT 1078.0500 0.0000 1078.1500 0.5200 ;
    END
  END out1[45]
  PIN out1[44]
    DIRECTION OUTPUT ;
    USE SIGNAL ;
    PORT
      LAYER M4 ;
        RECT 1074.0500 0.0000 1074.1500 0.5200 ;
    END
  END out1[44]
  PIN out1[43]
    DIRECTION OUTPUT ;
    USE SIGNAL ;
    PORT
      LAYER M4 ;
        RECT 1070.0500 0.0000 1070.1500 0.5200 ;
    END
  END out1[43]
  PIN out1[42]
    DIRECTION OUTPUT ;
    USE SIGNAL ;
    PORT
      LAYER M4 ;
        RECT 1066.0500 0.0000 1066.1500 0.5200 ;
    END
  END out1[42]
  PIN out1[41]
    DIRECTION OUTPUT ;
    USE SIGNAL ;
    PORT
      LAYER M4 ;
        RECT 1062.0500 0.0000 1062.1500 0.5200 ;
    END
  END out1[41]
  PIN out1[40]
    DIRECTION OUTPUT ;
    USE SIGNAL ;
    PORT
      LAYER M4 ;
        RECT 1058.0500 0.0000 1058.1500 0.5200 ;
    END
  END out1[40]
  PIN out1[39]
    DIRECTION OUTPUT ;
    USE SIGNAL ;
    PORT
      LAYER M4 ;
        RECT 1054.0500 0.0000 1054.1500 0.5200 ;
    END
  END out1[39]
  PIN out1[38]
    DIRECTION OUTPUT ;
    USE SIGNAL ;
    PORT
      LAYER M4 ;
        RECT 1050.0500 0.0000 1050.1500 0.5200 ;
    END
  END out1[38]
  PIN out1[37]
    DIRECTION OUTPUT ;
    USE SIGNAL ;
    PORT
      LAYER M4 ;
        RECT 1046.0500 0.0000 1046.1500 0.5200 ;
    END
  END out1[37]
  PIN out1[36]
    DIRECTION OUTPUT ;
    USE SIGNAL ;
    PORT
      LAYER M4 ;
        RECT 1042.0500 0.0000 1042.1500 0.5200 ;
    END
  END out1[36]
  PIN out1[35]
    DIRECTION OUTPUT ;
    USE SIGNAL ;
    PORT
      LAYER M4 ;
        RECT 1038.0500 0.0000 1038.1500 0.5200 ;
    END
  END out1[35]
  PIN out1[34]
    DIRECTION OUTPUT ;
    USE SIGNAL ;
    PORT
      LAYER M4 ;
        RECT 1034.0500 0.0000 1034.1500 0.5200 ;
    END
  END out1[34]
  PIN out1[33]
    DIRECTION OUTPUT ;
    USE SIGNAL ;
    PORT
      LAYER M4 ;
        RECT 1030.0500 0.0000 1030.1500 0.5200 ;
    END
  END out1[33]
  PIN out1[32]
    DIRECTION OUTPUT ;
    USE SIGNAL ;
    PORT
      LAYER M4 ;
        RECT 1026.0500 0.0000 1026.1500 0.5200 ;
    END
  END out1[32]
  PIN out1[31]
    DIRECTION OUTPUT ;
    USE SIGNAL ;
    PORT
      LAYER M4 ;
        RECT 1022.0500 0.0000 1022.1500 0.5200 ;
    END
  END out1[31]
  PIN out1[30]
    DIRECTION OUTPUT ;
    USE SIGNAL ;
    PORT
      LAYER M4 ;
        RECT 1018.0500 0.0000 1018.1500 0.5200 ;
    END
  END out1[30]
  PIN out1[29]
    DIRECTION OUTPUT ;
    USE SIGNAL ;
    PORT
      LAYER M4 ;
        RECT 1014.0500 0.0000 1014.1500 0.5200 ;
    END
  END out1[29]
  PIN out1[28]
    DIRECTION OUTPUT ;
    USE SIGNAL ;
    PORT
      LAYER M4 ;
        RECT 1010.0500 0.0000 1010.1500 0.5200 ;
    END
  END out1[28]
  PIN out1[27]
    DIRECTION OUTPUT ;
    USE SIGNAL ;
    PORT
      LAYER M4 ;
        RECT 1006.0500 0.0000 1006.1500 0.5200 ;
    END
  END out1[27]
  PIN out1[26]
    DIRECTION OUTPUT ;
    USE SIGNAL ;
    PORT
      LAYER M4 ;
        RECT 1002.0500 0.0000 1002.1500 0.5200 ;
    END
  END out1[26]
  PIN out1[25]
    DIRECTION OUTPUT ;
    USE SIGNAL ;
    PORT
      LAYER M4 ;
        RECT 998.0500 0.0000 998.1500 0.5200 ;
    END
  END out1[25]
  PIN out1[24]
    DIRECTION OUTPUT ;
    USE SIGNAL ;
    PORT
      LAYER M4 ;
        RECT 994.0500 0.0000 994.1500 0.5200 ;
    END
  END out1[24]
  PIN out1[23]
    DIRECTION OUTPUT ;
    USE SIGNAL ;
    PORT
      LAYER M4 ;
        RECT 990.0500 0.0000 990.1500 0.5200 ;
    END
  END out1[23]
  PIN out1[22]
    DIRECTION OUTPUT ;
    USE SIGNAL ;
    PORT
      LAYER M4 ;
        RECT 986.0500 0.0000 986.1500 0.5200 ;
    END
  END out1[22]
  PIN out1[21]
    DIRECTION OUTPUT ;
    USE SIGNAL ;
    PORT
      LAYER M4 ;
        RECT 982.0500 0.0000 982.1500 0.5200 ;
    END
  END out1[21]
  PIN out1[20]
    DIRECTION OUTPUT ;
    USE SIGNAL ;
    PORT
      LAYER M4 ;
        RECT 978.0500 0.0000 978.1500 0.5200 ;
    END
  END out1[20]
  PIN out1[19]
    DIRECTION OUTPUT ;
    USE SIGNAL ;
    PORT
      LAYER M4 ;
        RECT 974.0500 0.0000 974.1500 0.5200 ;
    END
  END out1[19]
  PIN out1[18]
    DIRECTION OUTPUT ;
    USE SIGNAL ;
    PORT
      LAYER M4 ;
        RECT 970.0500 0.0000 970.1500 0.5200 ;
    END
  END out1[18]
  PIN out1[17]
    DIRECTION OUTPUT ;
    USE SIGNAL ;
    PORT
      LAYER M4 ;
        RECT 966.0500 0.0000 966.1500 0.5200 ;
    END
  END out1[17]
  PIN out1[16]
    DIRECTION OUTPUT ;
    USE SIGNAL ;
    PORT
      LAYER M4 ;
        RECT 962.0500 0.0000 962.1500 0.5200 ;
    END
  END out1[16]
  PIN out1[15]
    DIRECTION OUTPUT ;
    USE SIGNAL ;
    PORT
      LAYER M4 ;
        RECT 958.0500 0.0000 958.1500 0.5200 ;
    END
  END out1[15]
  PIN out1[14]
    DIRECTION OUTPUT ;
    USE SIGNAL ;
    PORT
      LAYER M4 ;
        RECT 954.0500 0.0000 954.1500 0.5200 ;
    END
  END out1[14]
  PIN out1[13]
    DIRECTION OUTPUT ;
    USE SIGNAL ;
    PORT
      LAYER M4 ;
        RECT 950.0500 0.0000 950.1500 0.5200 ;
    END
  END out1[13]
  PIN out1[12]
    DIRECTION OUTPUT ;
    USE SIGNAL ;
    PORT
      LAYER M4 ;
        RECT 946.0500 0.0000 946.1500 0.5200 ;
    END
  END out1[12]
  PIN out1[11]
    DIRECTION OUTPUT ;
    USE SIGNAL ;
    PORT
      LAYER M4 ;
        RECT 942.0500 0.0000 942.1500 0.5200 ;
    END
  END out1[11]
  PIN out1[10]
    DIRECTION OUTPUT ;
    USE SIGNAL ;
    PORT
      LAYER M4 ;
        RECT 938.0500 0.0000 938.1500 0.5200 ;
    END
  END out1[10]
  PIN out1[9]
    DIRECTION OUTPUT ;
    USE SIGNAL ;
    PORT
      LAYER M4 ;
        RECT 934.0500 0.0000 934.1500 0.5200 ;
    END
  END out1[9]
  PIN out1[8]
    DIRECTION OUTPUT ;
    USE SIGNAL ;
    PORT
      LAYER M4 ;
        RECT 930.0500 0.0000 930.1500 0.5200 ;
    END
  END out1[8]
  PIN out1[7]
    DIRECTION OUTPUT ;
    USE SIGNAL ;
    PORT
      LAYER M4 ;
        RECT 926.0500 0.0000 926.1500 0.5200 ;
    END
  END out1[7]
  PIN out1[6]
    DIRECTION OUTPUT ;
    USE SIGNAL ;
    PORT
      LAYER M4 ;
        RECT 922.0500 0.0000 922.1500 0.5200 ;
    END
  END out1[6]
  PIN out1[5]
    DIRECTION OUTPUT ;
    USE SIGNAL ;
    PORT
      LAYER M4 ;
        RECT 918.0500 0.0000 918.1500 0.5200 ;
    END
  END out1[5]
  PIN out1[4]
    DIRECTION OUTPUT ;
    USE SIGNAL ;
    PORT
      LAYER M4 ;
        RECT 914.0500 0.0000 914.1500 0.5200 ;
    END
  END out1[4]
  PIN out1[3]
    DIRECTION OUTPUT ;
    USE SIGNAL ;
    PORT
      LAYER M4 ;
        RECT 910.0500 0.0000 910.1500 0.5200 ;
    END
  END out1[3]
  PIN out1[2]
    DIRECTION OUTPUT ;
    USE SIGNAL ;
    PORT
      LAYER M4 ;
        RECT 906.0500 0.0000 906.1500 0.5200 ;
    END
  END out1[2]
  PIN out1[1]
    DIRECTION OUTPUT ;
    USE SIGNAL ;
    PORT
      LAYER M4 ;
        RECT 902.0500 0.0000 902.1500 0.5200 ;
    END
  END out1[1]
  PIN out1[0]
    DIRECTION OUTPUT ;
    USE SIGNAL ;
    PORT
      LAYER M4 ;
        RECT 898.0500 0.0000 898.1500 0.5200 ;
    END
  END out1[0]
  PIN status0[3]
    DIRECTION OUTPUT ;
    USE SIGNAL ;
    PORT
      LAYER M4 ;
        RECT 894.0500 0.0000 894.1500 0.5200 ;
    END
  END status0[3]
  PIN status0[2]
    DIRECTION OUTPUT ;
    USE SIGNAL ;
    PORT
      LAYER M4 ;
        RECT 890.0500 0.0000 890.1500 0.5200 ;
    END
  END status0[2]
  PIN status0[1]
    DIRECTION OUTPUT ;
    USE SIGNAL ;
    PORT
      LAYER M4 ;
        RECT 886.0500 0.0000 886.1500 0.5200 ;
    END
  END status0[1]
  PIN status0[0]
    DIRECTION OUTPUT ;
    USE SIGNAL ;
    PORT
      LAYER M4 ;
        RECT 882.0500 0.0000 882.1500 0.5200 ;
    END
  END status0[0]
  PIN status1[3]
    DIRECTION OUTPUT ;
    USE SIGNAL ;
    PORT
      LAYER M4 ;
        RECT 878.0500 0.0000 878.1500 0.5200 ;
    END
  END status1[3]
  PIN status1[2]
    DIRECTION OUTPUT ;
    USE SIGNAL ;
    PORT
      LAYER M4 ;
        RECT 874.0500 0.0000 874.1500 0.5200 ;
    END
  END status1[2]
  PIN status1[1]
    DIRECTION OUTPUT ;
    USE SIGNAL ;
    PORT
      LAYER M4 ;
        RECT 870.0500 0.0000 870.1500 0.5200 ;
    END
  END status1[1]
  PIN status1[0]
    DIRECTION OUTPUT ;
    USE SIGNAL ;
    PORT
      LAYER M4 ;
        RECT 866.0500 0.0000 866.1500 0.5200 ;
    END
  END status1[0]
  OBS
    LAYER M1 ;
      RECT 0.0000 0.0000 3040.0000 3040.0000 ;
    LAYER M2 ;
      RECT 0.0000 0.0000 3040.0000 3040.0000 ;
    LAYER M3 ;
      RECT 0.0000 0.0000 3040.0000 3040.0000 ;
    LAYER M4 ;
      RECT 0.0000 0.6200 3040.0000 3040.0000 ;
      RECT 2174.2500 0.0000 3040.0000 0.6200 ;
      RECT 2170.2500 0.0000 2173.9500 0.6200 ;
      RECT 2166.2500 0.0000 2169.9500 0.6200 ;
      RECT 2162.2500 0.0000 2165.9500 0.6200 ;
      RECT 2158.2500 0.0000 2161.9500 0.6200 ;
      RECT 2154.2500 0.0000 2157.9500 0.6200 ;
      RECT 2150.2500 0.0000 2153.9500 0.6200 ;
      RECT 2146.2500 0.0000 2149.9500 0.6200 ;
      RECT 2142.2500 0.0000 2145.9500 0.6200 ;
      RECT 2138.2500 0.0000 2141.9500 0.6200 ;
      RECT 2134.2500 0.0000 2137.9500 0.6200 ;
      RECT 2130.2500 0.0000 2133.9500 0.6200 ;
      RECT 2126.2500 0.0000 2129.9500 0.6200 ;
      RECT 2122.2500 0.0000 2125.9500 0.6200 ;
      RECT 2118.2500 0.0000 2121.9500 0.6200 ;
      RECT 2114.2500 0.0000 2117.9500 0.6200 ;
      RECT 2110.2500 0.0000 2113.9500 0.6200 ;
      RECT 2106.2500 0.0000 2109.9500 0.6200 ;
      RECT 2102.2500 0.0000 2105.9500 0.6200 ;
      RECT 2098.2500 0.0000 2101.9500 0.6200 ;
      RECT 2094.2500 0.0000 2097.9500 0.6200 ;
      RECT 2090.2500 0.0000 2093.9500 0.6200 ;
      RECT 2086.2500 0.0000 2089.9500 0.6200 ;
      RECT 2082.2500 0.0000 2085.9500 0.6200 ;
      RECT 2078.2500 0.0000 2081.9500 0.6200 ;
      RECT 2074.2500 0.0000 2077.9500 0.6200 ;
      RECT 2070.2500 0.0000 2073.9500 0.6200 ;
      RECT 2066.2500 0.0000 2069.9500 0.6200 ;
      RECT 2062.2500 0.0000 2065.9500 0.6200 ;
      RECT 2058.2500 0.0000 2061.9500 0.6200 ;
      RECT 2054.2500 0.0000 2057.9500 0.6200 ;
      RECT 2050.2500 0.0000 2053.9500 0.6200 ;
      RECT 2046.2500 0.0000 2049.9500 0.6200 ;
      RECT 2042.2500 0.0000 2045.9500 0.6200 ;
      RECT 2038.2500 0.0000 2041.9500 0.6200 ;
      RECT 2034.2500 0.0000 2037.9500 0.6200 ;
      RECT 2030.2500 0.0000 2033.9500 0.6200 ;
      RECT 2026.2500 0.0000 2029.9500 0.6200 ;
      RECT 2022.2500 0.0000 2025.9500 0.6200 ;
      RECT 2018.2500 0.0000 2021.9500 0.6200 ;
      RECT 2014.2500 0.0000 2017.9500 0.6200 ;
      RECT 2010.2500 0.0000 2013.9500 0.6200 ;
      RECT 2006.2500 0.0000 2009.9500 0.6200 ;
      RECT 2002.2500 0.0000 2005.9500 0.6200 ;
      RECT 1998.2500 0.0000 2001.9500 0.6200 ;
      RECT 1994.2500 0.0000 1997.9500 0.6200 ;
      RECT 1990.2500 0.0000 1993.9500 0.6200 ;
      RECT 1986.2500 0.0000 1989.9500 0.6200 ;
      RECT 1982.2500 0.0000 1985.9500 0.6200 ;
      RECT 1978.2500 0.0000 1981.9500 0.6200 ;
      RECT 1974.2500 0.0000 1977.9500 0.6200 ;
      RECT 1970.2500 0.0000 1973.9500 0.6200 ;
      RECT 1966.2500 0.0000 1969.9500 0.6200 ;
      RECT 1962.2500 0.0000 1965.9500 0.6200 ;
      RECT 1958.2500 0.0000 1961.9500 0.6200 ;
      RECT 1954.2500 0.0000 1957.9500 0.6200 ;
      RECT 1950.2500 0.0000 1953.9500 0.6200 ;
      RECT 1946.2500 0.0000 1949.9500 0.6200 ;
      RECT 1942.2500 0.0000 1945.9500 0.6200 ;
      RECT 1938.2500 0.0000 1941.9500 0.6200 ;
      RECT 1934.2500 0.0000 1937.9500 0.6200 ;
      RECT 1930.2500 0.0000 1933.9500 0.6200 ;
      RECT 1926.2500 0.0000 1929.9500 0.6200 ;
      RECT 1922.2500 0.0000 1925.9500 0.6200 ;
      RECT 1918.2500 0.0000 1921.9500 0.6200 ;
      RECT 1914.2500 0.0000 1917.9500 0.6200 ;
      RECT 1910.2500 0.0000 1913.9500 0.6200 ;
      RECT 1906.2500 0.0000 1909.9500 0.6200 ;
      RECT 1902.2500 0.0000 1905.9500 0.6200 ;
      RECT 1898.2500 0.0000 1901.9500 0.6200 ;
      RECT 1894.2500 0.0000 1897.9500 0.6200 ;
      RECT 1890.2500 0.0000 1893.9500 0.6200 ;
      RECT 1886.2500 0.0000 1889.9500 0.6200 ;
      RECT 1882.2500 0.0000 1885.9500 0.6200 ;
      RECT 1878.2500 0.0000 1881.9500 0.6200 ;
      RECT 1874.2500 0.0000 1877.9500 0.6200 ;
      RECT 1870.2500 0.0000 1873.9500 0.6200 ;
      RECT 1866.2500 0.0000 1869.9500 0.6200 ;
      RECT 1862.2500 0.0000 1865.9500 0.6200 ;
      RECT 1858.2500 0.0000 1861.9500 0.6200 ;
      RECT 1854.2500 0.0000 1857.9500 0.6200 ;
      RECT 1850.2500 0.0000 1853.9500 0.6200 ;
      RECT 1846.2500 0.0000 1849.9500 0.6200 ;
      RECT 1842.2500 0.0000 1845.9500 0.6200 ;
      RECT 1838.2500 0.0000 1841.9500 0.6200 ;
      RECT 1834.2500 0.0000 1837.9500 0.6200 ;
      RECT 1830.2500 0.0000 1833.9500 0.6200 ;
      RECT 1826.2500 0.0000 1829.9500 0.6200 ;
      RECT 1822.2500 0.0000 1825.9500 0.6200 ;
      RECT 1818.2500 0.0000 1821.9500 0.6200 ;
      RECT 1814.2500 0.0000 1817.9500 0.6200 ;
      RECT 1810.2500 0.0000 1813.9500 0.6200 ;
      RECT 1806.2500 0.0000 1809.9500 0.6200 ;
      RECT 1802.2500 0.0000 1805.9500 0.6200 ;
      RECT 1798.2500 0.0000 1801.9500 0.6200 ;
      RECT 1794.2500 0.0000 1797.9500 0.6200 ;
      RECT 1790.2500 0.0000 1793.9500 0.6200 ;
      RECT 1786.2500 0.0000 1789.9500 0.6200 ;
      RECT 1782.2500 0.0000 1785.9500 0.6200 ;
      RECT 1778.2500 0.0000 1781.9500 0.6200 ;
      RECT 1774.2500 0.0000 1777.9500 0.6200 ;
      RECT 1770.2500 0.0000 1773.9500 0.6200 ;
      RECT 1766.2500 0.0000 1769.9500 0.6200 ;
      RECT 1762.2500 0.0000 1765.9500 0.6200 ;
      RECT 1758.2500 0.0000 1761.9500 0.6200 ;
      RECT 1754.2500 0.0000 1757.9500 0.6200 ;
      RECT 1750.2500 0.0000 1753.9500 0.6200 ;
      RECT 1746.2500 0.0000 1749.9500 0.6200 ;
      RECT 1742.2500 0.0000 1745.9500 0.6200 ;
      RECT 1738.2500 0.0000 1741.9500 0.6200 ;
      RECT 1734.2500 0.0000 1737.9500 0.6200 ;
      RECT 1730.2500 0.0000 1733.9500 0.6200 ;
      RECT 1726.2500 0.0000 1729.9500 0.6200 ;
      RECT 1722.2500 0.0000 1725.9500 0.6200 ;
      RECT 1718.2500 0.0000 1721.9500 0.6200 ;
      RECT 1714.2500 0.0000 1717.9500 0.6200 ;
      RECT 1710.2500 0.0000 1713.9500 0.6200 ;
      RECT 1706.2500 0.0000 1709.9500 0.6200 ;
      RECT 1702.2500 0.0000 1705.9500 0.6200 ;
      RECT 1698.2500 0.0000 1701.9500 0.6200 ;
      RECT 1694.2500 0.0000 1697.9500 0.6200 ;
      RECT 1690.2500 0.0000 1693.9500 0.6200 ;
      RECT 1686.2500 0.0000 1689.9500 0.6200 ;
      RECT 1682.2500 0.0000 1685.9500 0.6200 ;
      RECT 1678.2500 0.0000 1681.9500 0.6200 ;
      RECT 1674.2500 0.0000 1677.9500 0.6200 ;
      RECT 1670.2500 0.0000 1673.9500 0.6200 ;
      RECT 1666.2500 0.0000 1669.9500 0.6200 ;
      RECT 1662.2500 0.0000 1665.9500 0.6200 ;
      RECT 1658.2500 0.0000 1661.9500 0.6200 ;
      RECT 1654.2500 0.0000 1657.9500 0.6200 ;
      RECT 1650.2500 0.0000 1653.9500 0.6200 ;
      RECT 1646.2500 0.0000 1649.9500 0.6200 ;
      RECT 1642.2500 0.0000 1645.9500 0.6200 ;
      RECT 1638.2500 0.0000 1641.9500 0.6200 ;
      RECT 1634.2500 0.0000 1637.9500 0.6200 ;
      RECT 1630.2500 0.0000 1633.9500 0.6200 ;
      RECT 1626.2500 0.0000 1629.9500 0.6200 ;
      RECT 1622.2500 0.0000 1625.9500 0.6200 ;
      RECT 1618.2500 0.0000 1621.9500 0.6200 ;
      RECT 1614.2500 0.0000 1617.9500 0.6200 ;
      RECT 1610.2500 0.0000 1613.9500 0.6200 ;
      RECT 1606.2500 0.0000 1609.9500 0.6200 ;
      RECT 1602.2500 0.0000 1605.9500 0.6200 ;
      RECT 1598.2500 0.0000 1601.9500 0.6200 ;
      RECT 1594.2500 0.0000 1597.9500 0.6200 ;
      RECT 1590.2500 0.0000 1593.9500 0.6200 ;
      RECT 1586.2500 0.0000 1589.9500 0.6200 ;
      RECT 1582.2500 0.0000 1585.9500 0.6200 ;
      RECT 1578.2500 0.0000 1581.9500 0.6200 ;
      RECT 1574.2500 0.0000 1577.9500 0.6200 ;
      RECT 1570.2500 0.0000 1573.9500 0.6200 ;
      RECT 1566.2500 0.0000 1569.9500 0.6200 ;
      RECT 1562.2500 0.0000 1565.9500 0.6200 ;
      RECT 1558.2500 0.0000 1561.9500 0.6200 ;
      RECT 1554.2500 0.0000 1557.9500 0.6200 ;
      RECT 1550.2500 0.0000 1553.9500 0.6200 ;
      RECT 1546.2500 0.0000 1549.9500 0.6200 ;
      RECT 1542.2500 0.0000 1545.9500 0.6200 ;
      RECT 1538.2500 0.0000 1541.9500 0.6200 ;
      RECT 1534.2500 0.0000 1537.9500 0.6200 ;
      RECT 1530.2500 0.0000 1533.9500 0.6200 ;
      RECT 1526.2500 0.0000 1529.9500 0.6200 ;
      RECT 1522.2500 0.0000 1525.9500 0.6200 ;
      RECT 1518.2500 0.0000 1521.9500 0.6200 ;
      RECT 1514.2500 0.0000 1517.9500 0.6200 ;
      RECT 1510.2500 0.0000 1513.9500 0.6200 ;
      RECT 1506.2500 0.0000 1509.9500 0.6200 ;
      RECT 1502.2500 0.0000 1505.9500 0.6200 ;
      RECT 1498.2500 0.0000 1501.9500 0.6200 ;
      RECT 1494.2500 0.0000 1497.9500 0.6200 ;
      RECT 1490.2500 0.0000 1493.9500 0.6200 ;
      RECT 1486.2500 0.0000 1489.9500 0.6200 ;
      RECT 1482.2500 0.0000 1485.9500 0.6200 ;
      RECT 1478.2500 0.0000 1481.9500 0.6200 ;
      RECT 1474.2500 0.0000 1477.9500 0.6200 ;
      RECT 1470.2500 0.0000 1473.9500 0.6200 ;
      RECT 1466.2500 0.0000 1469.9500 0.6200 ;
      RECT 1462.2500 0.0000 1465.9500 0.6200 ;
      RECT 1458.2500 0.0000 1461.9500 0.6200 ;
      RECT 1454.2500 0.0000 1457.9500 0.6200 ;
      RECT 1450.2500 0.0000 1453.9500 0.6200 ;
      RECT 1446.2500 0.0000 1449.9500 0.6200 ;
      RECT 1442.2500 0.0000 1445.9500 0.6200 ;
      RECT 1438.2500 0.0000 1441.9500 0.6200 ;
      RECT 1434.2500 0.0000 1437.9500 0.6200 ;
      RECT 1430.2500 0.0000 1433.9500 0.6200 ;
      RECT 1426.2500 0.0000 1429.9500 0.6200 ;
      RECT 1422.2500 0.0000 1425.9500 0.6200 ;
      RECT 1418.2500 0.0000 1421.9500 0.6200 ;
      RECT 1414.2500 0.0000 1417.9500 0.6200 ;
      RECT 1410.2500 0.0000 1413.9500 0.6200 ;
      RECT 1406.2500 0.0000 1409.9500 0.6200 ;
      RECT 1402.2500 0.0000 1405.9500 0.6200 ;
      RECT 1398.2500 0.0000 1401.9500 0.6200 ;
      RECT 1394.2500 0.0000 1397.9500 0.6200 ;
      RECT 1390.2500 0.0000 1393.9500 0.6200 ;
      RECT 1386.2500 0.0000 1389.9500 0.6200 ;
      RECT 1382.2500 0.0000 1385.9500 0.6200 ;
      RECT 1378.2500 0.0000 1381.9500 0.6200 ;
      RECT 1374.2500 0.0000 1377.9500 0.6200 ;
      RECT 1370.2500 0.0000 1373.9500 0.6200 ;
      RECT 1366.2500 0.0000 1369.9500 0.6200 ;
      RECT 1362.2500 0.0000 1365.9500 0.6200 ;
      RECT 1358.2500 0.0000 1361.9500 0.6200 ;
      RECT 1354.2500 0.0000 1357.9500 0.6200 ;
      RECT 1350.2500 0.0000 1353.9500 0.6200 ;
      RECT 1346.2500 0.0000 1349.9500 0.6200 ;
      RECT 1342.2500 0.0000 1345.9500 0.6200 ;
      RECT 1338.2500 0.0000 1341.9500 0.6200 ;
      RECT 1334.2500 0.0000 1337.9500 0.6200 ;
      RECT 1330.2500 0.0000 1333.9500 0.6200 ;
      RECT 1326.2500 0.0000 1329.9500 0.6200 ;
      RECT 1322.2500 0.0000 1325.9500 0.6200 ;
      RECT 1318.2500 0.0000 1321.9500 0.6200 ;
      RECT 1314.2500 0.0000 1317.9500 0.6200 ;
      RECT 1310.2500 0.0000 1313.9500 0.6200 ;
      RECT 1306.2500 0.0000 1309.9500 0.6200 ;
      RECT 1302.2500 0.0000 1305.9500 0.6200 ;
      RECT 1298.2500 0.0000 1301.9500 0.6200 ;
      RECT 1294.2500 0.0000 1297.9500 0.6200 ;
      RECT 1290.2500 0.0000 1293.9500 0.6200 ;
      RECT 1286.2500 0.0000 1289.9500 0.6200 ;
      RECT 1282.2500 0.0000 1285.9500 0.6200 ;
      RECT 1278.2500 0.0000 1281.9500 0.6200 ;
      RECT 1274.2500 0.0000 1277.9500 0.6200 ;
      RECT 1270.2500 0.0000 1273.9500 0.6200 ;
      RECT 1266.2500 0.0000 1269.9500 0.6200 ;
      RECT 1262.2500 0.0000 1265.9500 0.6200 ;
      RECT 1258.2500 0.0000 1261.9500 0.6200 ;
      RECT 1254.2500 0.0000 1257.9500 0.6200 ;
      RECT 1250.2500 0.0000 1253.9500 0.6200 ;
      RECT 1246.2500 0.0000 1249.9500 0.6200 ;
      RECT 1242.2500 0.0000 1245.9500 0.6200 ;
      RECT 1238.2500 0.0000 1241.9500 0.6200 ;
      RECT 1234.2500 0.0000 1237.9500 0.6200 ;
      RECT 1230.2500 0.0000 1233.9500 0.6200 ;
      RECT 1226.2500 0.0000 1229.9500 0.6200 ;
      RECT 1222.2500 0.0000 1225.9500 0.6200 ;
      RECT 1218.2500 0.0000 1221.9500 0.6200 ;
      RECT 1214.2500 0.0000 1217.9500 0.6200 ;
      RECT 1210.2500 0.0000 1213.9500 0.6200 ;
      RECT 1206.2500 0.0000 1209.9500 0.6200 ;
      RECT 1202.2500 0.0000 1205.9500 0.6200 ;
      RECT 1198.2500 0.0000 1201.9500 0.6200 ;
      RECT 1194.2500 0.0000 1197.9500 0.6200 ;
      RECT 1190.2500 0.0000 1193.9500 0.6200 ;
      RECT 1186.2500 0.0000 1189.9500 0.6200 ;
      RECT 1182.2500 0.0000 1185.9500 0.6200 ;
      RECT 1178.2500 0.0000 1181.9500 0.6200 ;
      RECT 1174.2500 0.0000 1177.9500 0.6200 ;
      RECT 1170.2500 0.0000 1173.9500 0.6200 ;
      RECT 1166.2500 0.0000 1169.9500 0.6200 ;
      RECT 1162.2500 0.0000 1165.9500 0.6200 ;
      RECT 1158.2500 0.0000 1161.9500 0.6200 ;
      RECT 1154.2500 0.0000 1157.9500 0.6200 ;
      RECT 1150.2500 0.0000 1153.9500 0.6200 ;
      RECT 1146.2500 0.0000 1149.9500 0.6200 ;
      RECT 1142.2500 0.0000 1145.9500 0.6200 ;
      RECT 1138.2500 0.0000 1141.9500 0.6200 ;
      RECT 1134.2500 0.0000 1137.9500 0.6200 ;
      RECT 1130.2500 0.0000 1133.9500 0.6200 ;
      RECT 1126.2500 0.0000 1129.9500 0.6200 ;
      RECT 1122.2500 0.0000 1125.9500 0.6200 ;
      RECT 1118.2500 0.0000 1121.9500 0.6200 ;
      RECT 1114.2500 0.0000 1117.9500 0.6200 ;
      RECT 1110.2500 0.0000 1113.9500 0.6200 ;
      RECT 1106.2500 0.0000 1109.9500 0.6200 ;
      RECT 1102.2500 0.0000 1105.9500 0.6200 ;
      RECT 1098.2500 0.0000 1101.9500 0.6200 ;
      RECT 1094.2500 0.0000 1097.9500 0.6200 ;
      RECT 1090.2500 0.0000 1093.9500 0.6200 ;
      RECT 1086.2500 0.0000 1089.9500 0.6200 ;
      RECT 1082.2500 0.0000 1085.9500 0.6200 ;
      RECT 1078.2500 0.0000 1081.9500 0.6200 ;
      RECT 1074.2500 0.0000 1077.9500 0.6200 ;
      RECT 1070.2500 0.0000 1073.9500 0.6200 ;
      RECT 1066.2500 0.0000 1069.9500 0.6200 ;
      RECT 1062.2500 0.0000 1065.9500 0.6200 ;
      RECT 1058.2500 0.0000 1061.9500 0.6200 ;
      RECT 1054.2500 0.0000 1057.9500 0.6200 ;
      RECT 1050.2500 0.0000 1053.9500 0.6200 ;
      RECT 1046.2500 0.0000 1049.9500 0.6200 ;
      RECT 1042.2500 0.0000 1045.9500 0.6200 ;
      RECT 1038.2500 0.0000 1041.9500 0.6200 ;
      RECT 1034.2500 0.0000 1037.9500 0.6200 ;
      RECT 1030.2500 0.0000 1033.9500 0.6200 ;
      RECT 1026.2500 0.0000 1029.9500 0.6200 ;
      RECT 1022.2500 0.0000 1025.9500 0.6200 ;
      RECT 1018.2500 0.0000 1021.9500 0.6200 ;
      RECT 1014.2500 0.0000 1017.9500 0.6200 ;
      RECT 1010.2500 0.0000 1013.9500 0.6200 ;
      RECT 1006.2500 0.0000 1009.9500 0.6200 ;
      RECT 1002.2500 0.0000 1005.9500 0.6200 ;
      RECT 998.2500 0.0000 1001.9500 0.6200 ;
      RECT 994.2500 0.0000 997.9500 0.6200 ;
      RECT 990.2500 0.0000 993.9500 0.6200 ;
      RECT 986.2500 0.0000 989.9500 0.6200 ;
      RECT 982.2500 0.0000 985.9500 0.6200 ;
      RECT 978.2500 0.0000 981.9500 0.6200 ;
      RECT 974.2500 0.0000 977.9500 0.6200 ;
      RECT 970.2500 0.0000 973.9500 0.6200 ;
      RECT 966.2500 0.0000 969.9500 0.6200 ;
      RECT 962.2500 0.0000 965.9500 0.6200 ;
      RECT 958.2500 0.0000 961.9500 0.6200 ;
      RECT 954.2500 0.0000 957.9500 0.6200 ;
      RECT 950.2500 0.0000 953.9500 0.6200 ;
      RECT 946.2500 0.0000 949.9500 0.6200 ;
      RECT 942.2500 0.0000 945.9500 0.6200 ;
      RECT 938.2500 0.0000 941.9500 0.6200 ;
      RECT 934.2500 0.0000 937.9500 0.6200 ;
      RECT 930.2500 0.0000 933.9500 0.6200 ;
      RECT 926.2500 0.0000 929.9500 0.6200 ;
      RECT 922.2500 0.0000 925.9500 0.6200 ;
      RECT 918.2500 0.0000 921.9500 0.6200 ;
      RECT 914.2500 0.0000 917.9500 0.6200 ;
      RECT 910.2500 0.0000 913.9500 0.6200 ;
      RECT 906.2500 0.0000 909.9500 0.6200 ;
      RECT 902.2500 0.0000 905.9500 0.6200 ;
      RECT 898.2500 0.0000 901.9500 0.6200 ;
      RECT 894.2500 0.0000 897.9500 0.6200 ;
      RECT 890.2500 0.0000 893.9500 0.6200 ;
      RECT 886.2500 0.0000 889.9500 0.6200 ;
      RECT 882.2500 0.0000 885.9500 0.6200 ;
      RECT 878.2500 0.0000 881.9500 0.6200 ;
      RECT 874.2500 0.0000 877.9500 0.6200 ;
      RECT 870.2500 0.0000 873.9500 0.6200 ;
      RECT 866.2500 0.0000 869.9500 0.6200 ;
      RECT 0.0000 0.0000 865.9500 0.6200 ;
    LAYER M5 ;
      RECT 0.0000 1902.3500 3040.0000 3040.0000 ;
      RECT 0.6200 1902.0500 3040.0000 1902.3500 ;
      RECT 0.0000 1897.3500 3040.0000 1902.0500 ;
      RECT 0.6200 1897.0500 3040.0000 1897.3500 ;
      RECT 0.0000 1892.3500 3040.0000 1897.0500 ;
      RECT 0.6200 1892.0500 3040.0000 1892.3500 ;
      RECT 0.0000 1887.3500 3040.0000 1892.0500 ;
      RECT 0.6200 1887.0500 3040.0000 1887.3500 ;
      RECT 0.0000 1882.3500 3040.0000 1887.0500 ;
      RECT 0.6200 1882.0500 3040.0000 1882.3500 ;
      RECT 0.0000 1877.3500 3040.0000 1882.0500 ;
      RECT 0.6200 1877.0500 3040.0000 1877.3500 ;
      RECT 0.0000 1872.3500 3040.0000 1877.0500 ;
      RECT 0.6200 1872.0500 3040.0000 1872.3500 ;
      RECT 0.0000 1867.3500 3040.0000 1872.0500 ;
      RECT 0.6200 1867.0500 3040.0000 1867.3500 ;
      RECT 0.0000 1862.3500 3040.0000 1867.0500 ;
      RECT 0.6200 1862.0500 3040.0000 1862.3500 ;
      RECT 0.0000 1857.3500 3040.0000 1862.0500 ;
      RECT 0.6200 1857.0500 3040.0000 1857.3500 ;
      RECT 0.0000 1852.3500 3040.0000 1857.0500 ;
      RECT 0.6200 1852.0500 3040.0000 1852.3500 ;
      RECT 0.0000 1847.3500 3040.0000 1852.0500 ;
      RECT 0.6200 1847.0500 3040.0000 1847.3500 ;
      RECT 0.0000 1842.3500 3040.0000 1847.0500 ;
      RECT 0.6200 1842.0500 3040.0000 1842.3500 ;
      RECT 0.0000 1837.3500 3040.0000 1842.0500 ;
      RECT 0.6200 1837.0500 3040.0000 1837.3500 ;
      RECT 0.0000 1832.3500 3040.0000 1837.0500 ;
      RECT 0.6200 1832.0500 3040.0000 1832.3500 ;
      RECT 0.0000 1827.3500 3040.0000 1832.0500 ;
      RECT 0.6200 1827.0500 3040.0000 1827.3500 ;
      RECT 0.0000 1822.3500 3040.0000 1827.0500 ;
      RECT 0.6200 1822.0500 3040.0000 1822.3500 ;
      RECT 0.0000 1817.3500 3040.0000 1822.0500 ;
      RECT 0.6200 1817.0500 3040.0000 1817.3500 ;
      RECT 0.0000 1812.3500 3040.0000 1817.0500 ;
      RECT 0.6200 1812.0500 3040.0000 1812.3500 ;
      RECT 0.0000 1807.3500 3040.0000 1812.0500 ;
      RECT 0.6200 1807.0500 3040.0000 1807.3500 ;
      RECT 0.0000 1802.3500 3040.0000 1807.0500 ;
      RECT 0.6200 1802.0500 3040.0000 1802.3500 ;
      RECT 0.0000 1797.3500 3040.0000 1802.0500 ;
      RECT 0.6200 1797.0500 3040.0000 1797.3500 ;
      RECT 0.0000 1792.3500 3040.0000 1797.0500 ;
      RECT 0.6200 1792.0500 3040.0000 1792.3500 ;
      RECT 0.0000 1787.3500 3040.0000 1792.0500 ;
      RECT 0.6200 1787.0500 3040.0000 1787.3500 ;
      RECT 0.0000 1782.3500 3040.0000 1787.0500 ;
      RECT 0.6200 1782.0500 3040.0000 1782.3500 ;
      RECT 0.0000 1777.3500 3040.0000 1782.0500 ;
      RECT 0.6200 1777.0500 3040.0000 1777.3500 ;
      RECT 0.0000 1772.3500 3040.0000 1777.0500 ;
      RECT 0.6200 1772.0500 3040.0000 1772.3500 ;
      RECT 0.0000 1767.3500 3040.0000 1772.0500 ;
      RECT 0.6200 1767.0500 3040.0000 1767.3500 ;
      RECT 0.0000 1762.3500 3040.0000 1767.0500 ;
      RECT 0.6200 1762.0500 3040.0000 1762.3500 ;
      RECT 0.0000 1757.3500 3040.0000 1762.0500 ;
      RECT 0.6200 1757.0500 3040.0000 1757.3500 ;
      RECT 0.0000 1752.3500 3040.0000 1757.0500 ;
      RECT 0.6200 1752.0500 3040.0000 1752.3500 ;
      RECT 0.0000 1747.3500 3040.0000 1752.0500 ;
      RECT 0.6200 1747.0500 3040.0000 1747.3500 ;
      RECT 0.0000 1742.3500 3040.0000 1747.0500 ;
      RECT 0.6200 1742.0500 3040.0000 1742.3500 ;
      RECT 0.0000 1737.3500 3040.0000 1742.0500 ;
      RECT 0.6200 1737.0500 3040.0000 1737.3500 ;
      RECT 0.0000 1732.3500 3040.0000 1737.0500 ;
      RECT 0.6200 1732.0500 3040.0000 1732.3500 ;
      RECT 0.0000 1727.3500 3040.0000 1732.0500 ;
      RECT 0.6200 1727.0500 3040.0000 1727.3500 ;
      RECT 0.0000 1722.3500 3040.0000 1727.0500 ;
      RECT 0.6200 1722.0500 3040.0000 1722.3500 ;
      RECT 0.0000 1717.3500 3040.0000 1722.0500 ;
      RECT 0.6200 1717.0500 3040.0000 1717.3500 ;
      RECT 0.0000 1712.3500 3040.0000 1717.0500 ;
      RECT 0.6200 1712.0500 3040.0000 1712.3500 ;
      RECT 0.0000 1707.3500 3040.0000 1712.0500 ;
      RECT 0.6200 1707.0500 3040.0000 1707.3500 ;
      RECT 0.0000 1702.3500 3040.0000 1707.0500 ;
      RECT 0.6200 1702.0500 3040.0000 1702.3500 ;
      RECT 0.0000 1697.3500 3040.0000 1702.0500 ;
      RECT 0.6200 1697.0500 3040.0000 1697.3500 ;
      RECT 0.0000 1692.3500 3040.0000 1697.0500 ;
      RECT 0.6200 1692.0500 3040.0000 1692.3500 ;
      RECT 0.0000 1687.3500 3040.0000 1692.0500 ;
      RECT 0.6200 1687.0500 3040.0000 1687.3500 ;
      RECT 0.0000 1682.3500 3040.0000 1687.0500 ;
      RECT 0.6200 1682.0500 3040.0000 1682.3500 ;
      RECT 0.0000 1677.3500 3040.0000 1682.0500 ;
      RECT 0.6200 1677.0500 3040.0000 1677.3500 ;
      RECT 0.0000 1672.3500 3040.0000 1677.0500 ;
      RECT 0.6200 1672.0500 3040.0000 1672.3500 ;
      RECT 0.0000 1667.3500 3040.0000 1672.0500 ;
      RECT 0.6200 1667.0500 3040.0000 1667.3500 ;
      RECT 0.0000 1662.3500 3040.0000 1667.0500 ;
      RECT 0.6200 1662.0500 3040.0000 1662.3500 ;
      RECT 0.0000 1657.3500 3040.0000 1662.0500 ;
      RECT 0.6200 1657.0500 3040.0000 1657.3500 ;
      RECT 0.0000 1652.3500 3040.0000 1657.0500 ;
      RECT 0.6200 1652.0500 3040.0000 1652.3500 ;
      RECT 0.0000 1647.3500 3040.0000 1652.0500 ;
      RECT 0.6200 1647.0500 3040.0000 1647.3500 ;
      RECT 0.0000 1642.3500 3040.0000 1647.0500 ;
      RECT 0.6200 1642.0500 3040.0000 1642.3500 ;
      RECT 0.0000 1637.3500 3040.0000 1642.0500 ;
      RECT 0.6200 1637.0500 3040.0000 1637.3500 ;
      RECT 0.0000 1632.3500 3040.0000 1637.0500 ;
      RECT 0.6200 1632.0500 3040.0000 1632.3500 ;
      RECT 0.0000 1627.3500 3040.0000 1632.0500 ;
      RECT 0.6200 1627.0500 3040.0000 1627.3500 ;
      RECT 0.0000 1622.3500 3040.0000 1627.0500 ;
      RECT 0.6200 1622.0500 3040.0000 1622.3500 ;
      RECT 0.0000 1617.3500 3040.0000 1622.0500 ;
      RECT 0.6200 1617.0500 3040.0000 1617.3500 ;
      RECT 0.0000 1612.3500 3040.0000 1617.0500 ;
      RECT 0.6200 1612.0500 3040.0000 1612.3500 ;
      RECT 0.0000 1607.3500 3040.0000 1612.0500 ;
      RECT 0.6200 1607.0500 3040.0000 1607.3500 ;
      RECT 0.0000 1602.3500 3040.0000 1607.0500 ;
      RECT 0.6200 1602.0500 3040.0000 1602.3500 ;
      RECT 0.0000 1597.3500 3040.0000 1602.0500 ;
      RECT 0.6200 1597.0500 3040.0000 1597.3500 ;
      RECT 0.0000 1592.3500 3040.0000 1597.0500 ;
      RECT 0.6200 1592.0500 3040.0000 1592.3500 ;
      RECT 0.0000 1587.3500 3040.0000 1592.0500 ;
      RECT 0.6200 1587.0500 3040.0000 1587.3500 ;
      RECT 0.0000 1582.3500 3040.0000 1587.0500 ;
      RECT 0.6200 1582.0500 3040.0000 1582.3500 ;
      RECT 0.0000 1577.3500 3040.0000 1582.0500 ;
      RECT 0.6200 1577.0500 3040.0000 1577.3500 ;
      RECT 0.0000 1572.3500 3040.0000 1577.0500 ;
      RECT 0.6200 1572.0500 3040.0000 1572.3500 ;
      RECT 0.0000 1567.3500 3040.0000 1572.0500 ;
      RECT 0.6200 1567.0500 3040.0000 1567.3500 ;
      RECT 0.0000 1562.3500 3040.0000 1567.0500 ;
      RECT 0.6200 1562.0500 3040.0000 1562.3500 ;
      RECT 0.0000 1557.3500 3040.0000 1562.0500 ;
      RECT 0.6200 1557.0500 3040.0000 1557.3500 ;
      RECT 0.0000 1552.3500 3040.0000 1557.0500 ;
      RECT 0.6200 1552.0500 3040.0000 1552.3500 ;
      RECT 0.0000 1547.3500 3040.0000 1552.0500 ;
      RECT 0.6200 1547.0500 3040.0000 1547.3500 ;
      RECT 0.0000 1542.3500 3040.0000 1547.0500 ;
      RECT 0.6200 1542.0500 3040.0000 1542.3500 ;
      RECT 0.0000 1537.3500 3040.0000 1542.0500 ;
      RECT 0.6200 1537.0500 3040.0000 1537.3500 ;
      RECT 0.0000 1532.3500 3040.0000 1537.0500 ;
      RECT 0.6200 1532.0500 3040.0000 1532.3500 ;
      RECT 0.0000 1527.3500 3040.0000 1532.0500 ;
      RECT 0.6200 1527.0500 3040.0000 1527.3500 ;
      RECT 0.0000 1522.3500 3040.0000 1527.0500 ;
      RECT 0.6200 1522.0500 3040.0000 1522.3500 ;
      RECT 0.0000 1517.3500 3040.0000 1522.0500 ;
      RECT 0.6200 1517.0500 3040.0000 1517.3500 ;
      RECT 0.0000 1512.3500 3040.0000 1517.0500 ;
      RECT 0.6200 1512.0500 3040.0000 1512.3500 ;
      RECT 0.0000 1507.3500 3040.0000 1512.0500 ;
      RECT 0.6200 1507.0500 3040.0000 1507.3500 ;
      RECT 0.0000 1502.3500 3040.0000 1507.0500 ;
      RECT 0.6200 1502.0500 3040.0000 1502.3500 ;
      RECT 0.0000 1497.3500 3040.0000 1502.0500 ;
      RECT 0.6200 1497.0500 3040.0000 1497.3500 ;
      RECT 0.0000 1492.3500 3040.0000 1497.0500 ;
      RECT 0.6200 1492.0500 3040.0000 1492.3500 ;
      RECT 0.0000 1487.3500 3040.0000 1492.0500 ;
      RECT 0.6200 1487.0500 3040.0000 1487.3500 ;
      RECT 0.0000 1482.3500 3040.0000 1487.0500 ;
      RECT 0.6200 1482.0500 3040.0000 1482.3500 ;
      RECT 0.0000 1477.3500 3040.0000 1482.0500 ;
      RECT 0.6200 1477.0500 3040.0000 1477.3500 ;
      RECT 0.0000 1472.3500 3040.0000 1477.0500 ;
      RECT 0.6200 1472.0500 3040.0000 1472.3500 ;
      RECT 0.0000 1467.3500 3040.0000 1472.0500 ;
      RECT 0.6200 1467.0500 3040.0000 1467.3500 ;
      RECT 0.0000 1462.3500 3040.0000 1467.0500 ;
      RECT 0.6200 1462.0500 3040.0000 1462.3500 ;
      RECT 0.0000 1457.3500 3040.0000 1462.0500 ;
      RECT 0.6200 1457.0500 3040.0000 1457.3500 ;
      RECT 0.0000 1452.3500 3040.0000 1457.0500 ;
      RECT 0.6200 1452.0500 3040.0000 1452.3500 ;
      RECT 0.0000 1447.3500 3040.0000 1452.0500 ;
      RECT 0.6200 1447.0500 3040.0000 1447.3500 ;
      RECT 0.0000 1442.3500 3040.0000 1447.0500 ;
      RECT 0.6200 1442.0500 3040.0000 1442.3500 ;
      RECT 0.0000 1437.3500 3040.0000 1442.0500 ;
      RECT 0.6200 1437.0500 3040.0000 1437.3500 ;
      RECT 0.0000 1432.3500 3040.0000 1437.0500 ;
      RECT 0.6200 1432.0500 3040.0000 1432.3500 ;
      RECT 0.0000 1427.3500 3040.0000 1432.0500 ;
      RECT 0.6200 1427.0500 3040.0000 1427.3500 ;
      RECT 0.0000 1422.3500 3040.0000 1427.0500 ;
      RECT 0.6200 1422.0500 3040.0000 1422.3500 ;
      RECT 0.0000 1417.3500 3040.0000 1422.0500 ;
      RECT 0.6200 1417.0500 3040.0000 1417.3500 ;
      RECT 0.0000 1412.3500 3040.0000 1417.0500 ;
      RECT 0.6200 1412.0500 3040.0000 1412.3500 ;
      RECT 0.0000 1407.3500 3040.0000 1412.0500 ;
      RECT 0.6200 1407.0500 3040.0000 1407.3500 ;
      RECT 0.0000 1402.3500 3040.0000 1407.0500 ;
      RECT 0.6200 1402.0500 3040.0000 1402.3500 ;
      RECT 0.0000 1397.3500 3040.0000 1402.0500 ;
      RECT 0.6200 1397.0500 3040.0000 1397.3500 ;
      RECT 0.0000 1392.3500 3040.0000 1397.0500 ;
      RECT 0.6200 1392.0500 3040.0000 1392.3500 ;
      RECT 0.0000 1387.3500 3040.0000 1392.0500 ;
      RECT 0.6200 1387.0500 3040.0000 1387.3500 ;
      RECT 0.0000 1382.3500 3040.0000 1387.0500 ;
      RECT 0.6200 1382.0500 3040.0000 1382.3500 ;
      RECT 0.0000 1377.3500 3040.0000 1382.0500 ;
      RECT 0.6200 1377.0500 3040.0000 1377.3500 ;
      RECT 0.0000 1372.3500 3040.0000 1377.0500 ;
      RECT 0.6200 1372.0500 3040.0000 1372.3500 ;
      RECT 0.0000 1367.3500 3040.0000 1372.0500 ;
      RECT 0.6200 1367.0500 3040.0000 1367.3500 ;
      RECT 0.0000 1362.3500 3040.0000 1367.0500 ;
      RECT 0.6200 1362.0500 3040.0000 1362.3500 ;
      RECT 0.0000 1357.3500 3040.0000 1362.0500 ;
      RECT 0.6200 1357.0500 3040.0000 1357.3500 ;
      RECT 0.0000 1352.3500 3040.0000 1357.0500 ;
      RECT 0.6200 1352.0500 3040.0000 1352.3500 ;
      RECT 0.0000 1347.3500 3040.0000 1352.0500 ;
      RECT 0.6200 1347.0500 3040.0000 1347.3500 ;
      RECT 0.0000 1342.3500 3040.0000 1347.0500 ;
      RECT 0.6200 1342.0500 3040.0000 1342.3500 ;
      RECT 0.0000 1337.3500 3040.0000 1342.0500 ;
      RECT 0.6200 1337.0500 3040.0000 1337.3500 ;
      RECT 0.0000 1332.3500 3040.0000 1337.0500 ;
      RECT 0.6200 1332.0500 3040.0000 1332.3500 ;
      RECT 0.0000 1327.3500 3040.0000 1332.0500 ;
      RECT 0.6200 1327.0500 3040.0000 1327.3500 ;
      RECT 0.0000 1322.3500 3040.0000 1327.0500 ;
      RECT 0.6200 1322.0500 3040.0000 1322.3500 ;
      RECT 0.0000 1317.3500 3040.0000 1322.0500 ;
      RECT 0.6200 1317.0500 3040.0000 1317.3500 ;
      RECT 0.0000 1312.3500 3040.0000 1317.0500 ;
      RECT 0.6200 1312.0500 3040.0000 1312.3500 ;
      RECT 0.0000 1307.3500 3040.0000 1312.0500 ;
      RECT 0.6200 1307.0500 3040.0000 1307.3500 ;
      RECT 0.0000 1302.3500 3040.0000 1307.0500 ;
      RECT 0.6200 1302.0500 3040.0000 1302.3500 ;
      RECT 0.0000 1297.3500 3040.0000 1302.0500 ;
      RECT 0.6200 1297.0500 3040.0000 1297.3500 ;
      RECT 0.0000 1292.3500 3040.0000 1297.0500 ;
      RECT 0.6200 1292.0500 3040.0000 1292.3500 ;
      RECT 0.0000 1287.3500 3040.0000 1292.0500 ;
      RECT 0.6200 1287.0500 3040.0000 1287.3500 ;
      RECT 0.0000 1282.3500 3040.0000 1287.0500 ;
      RECT 0.6200 1282.0500 3040.0000 1282.3500 ;
      RECT 0.0000 1277.3500 3040.0000 1282.0500 ;
      RECT 0.6200 1277.0500 3040.0000 1277.3500 ;
      RECT 0.0000 1272.3500 3040.0000 1277.0500 ;
      RECT 0.6200 1272.0500 3040.0000 1272.3500 ;
      RECT 0.0000 1267.3500 3040.0000 1272.0500 ;
      RECT 0.6200 1267.0500 3040.0000 1267.3500 ;
      RECT 0.0000 1262.3500 3040.0000 1267.0500 ;
      RECT 0.6200 1262.0500 3040.0000 1262.3500 ;
      RECT 0.0000 1257.3500 3040.0000 1262.0500 ;
      RECT 0.6200 1257.0500 3040.0000 1257.3500 ;
      RECT 0.0000 1252.3500 3040.0000 1257.0500 ;
      RECT 0.6200 1252.0500 3040.0000 1252.3500 ;
      RECT 0.0000 1247.3500 3040.0000 1252.0500 ;
      RECT 0.6200 1247.0500 3040.0000 1247.3500 ;
      RECT 0.0000 1242.3500 3040.0000 1247.0500 ;
      RECT 0.6200 1242.0500 3040.0000 1242.3500 ;
      RECT 0.0000 1237.3500 3040.0000 1242.0500 ;
      RECT 0.6200 1237.0500 3040.0000 1237.3500 ;
      RECT 0.0000 1232.3500 3040.0000 1237.0500 ;
      RECT 0.6200 1232.0500 3040.0000 1232.3500 ;
      RECT 0.0000 1227.3500 3040.0000 1232.0500 ;
      RECT 0.6200 1227.0500 3040.0000 1227.3500 ;
      RECT 0.0000 1222.3500 3040.0000 1227.0500 ;
      RECT 0.6200 1222.0500 3040.0000 1222.3500 ;
      RECT 0.0000 1217.3500 3040.0000 1222.0500 ;
      RECT 0.6200 1217.0500 3040.0000 1217.3500 ;
      RECT 0.0000 1212.3500 3040.0000 1217.0500 ;
      RECT 0.6200 1212.0500 3040.0000 1212.3500 ;
      RECT 0.0000 1207.3500 3040.0000 1212.0500 ;
      RECT 0.6200 1207.0500 3040.0000 1207.3500 ;
      RECT 0.0000 1202.3500 3040.0000 1207.0500 ;
      RECT 0.6200 1202.0500 3040.0000 1202.3500 ;
      RECT 0.0000 1197.3500 3040.0000 1202.0500 ;
      RECT 0.6200 1197.0500 3040.0000 1197.3500 ;
      RECT 0.0000 1192.3500 3040.0000 1197.0500 ;
      RECT 0.6200 1192.0500 3040.0000 1192.3500 ;
      RECT 0.0000 1187.3500 3040.0000 1192.0500 ;
      RECT 0.6200 1187.0500 3040.0000 1187.3500 ;
      RECT 0.0000 1182.3500 3040.0000 1187.0500 ;
      RECT 0.6200 1182.0500 3040.0000 1182.3500 ;
      RECT 0.0000 1177.3500 3040.0000 1182.0500 ;
      RECT 0.6200 1177.0500 3040.0000 1177.3500 ;
      RECT 0.0000 1172.3500 3040.0000 1177.0500 ;
      RECT 0.6200 1172.0500 3040.0000 1172.3500 ;
      RECT 0.0000 1167.3500 3040.0000 1172.0500 ;
      RECT 0.6200 1167.0500 3040.0000 1167.3500 ;
      RECT 0.0000 1162.3500 3040.0000 1167.0500 ;
      RECT 0.6200 1162.0500 3040.0000 1162.3500 ;
      RECT 0.0000 1157.3500 3040.0000 1162.0500 ;
      RECT 0.6200 1157.0500 3040.0000 1157.3500 ;
      RECT 0.0000 1152.3500 3040.0000 1157.0500 ;
      RECT 0.6200 1152.0500 3040.0000 1152.3500 ;
      RECT 0.0000 1147.3500 3040.0000 1152.0500 ;
      RECT 0.6200 1147.0500 3040.0000 1147.3500 ;
      RECT 0.0000 1142.3500 3040.0000 1147.0500 ;
      RECT 0.6200 1142.0500 3040.0000 1142.3500 ;
      RECT 0.0000 1137.3500 3040.0000 1142.0500 ;
      RECT 0.6200 1137.0500 3040.0000 1137.3500 ;
      RECT 0.0000 0.0000 3040.0000 1137.0500 ;
    LAYER M6 ;
      RECT 0.0000 0.0000 3040.0000 3040.0000 ;
    LAYER M7 ;
      RECT 0.0000 0.0000 3040.0000 3040.0000 ;
    LAYER M8 ;
      RECT 0.0000 0.0000 3040.0000 3040.0000 ;
  END
END fullchip

END LIBRARY
